VERSION 5.8 ;
BUSBITCHARS "[]" ;
DIVIDERCHAR "/" ;
UNITS
    DATABASE MICRONS 1000 ;
END UNITS

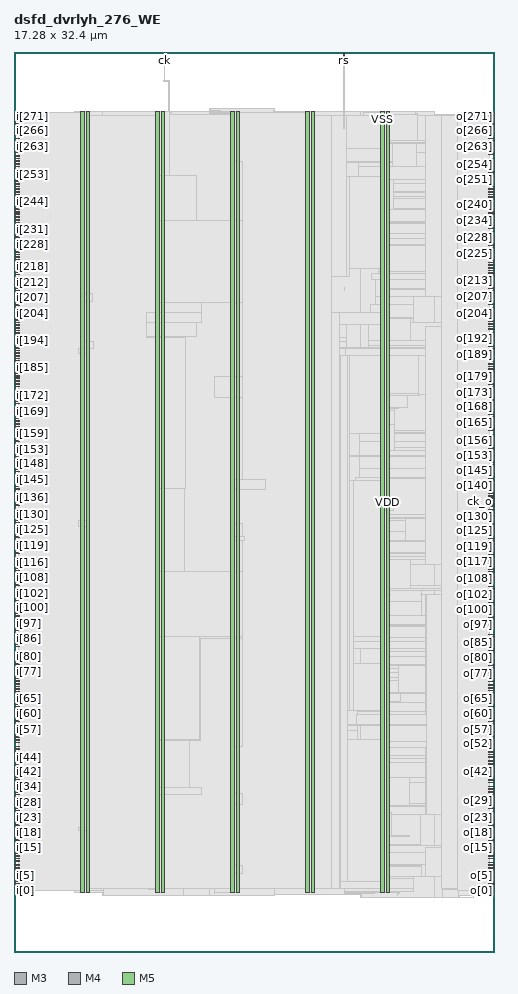
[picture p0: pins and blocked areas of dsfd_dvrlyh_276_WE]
MACRO dsfd_dvrlyh_276_WE
  FOREIGN dsfd_dvrlyh_276_WE 0 0 ;
  CLASS BLOCK ;
  SIZE 17.28 BY 32.4 ;
  PIN ck
    DIRECTION INPUT ;
    USE SIGNAL ;
    PORT
      LAYER M3 ;
        RECT  5.4 32.256 5.418 32.4 ;
    END
  END ck
  PIN ck_o
    DIRECTION OUTPUT ;
    USE SIGNAL ;
    PORT
      LAYER M4 ;
        RECT  17.088 16.224 17.28 16.248 ;
    END
  END ck_o
  PIN i[0]
    DIRECTION INPUT ;
    USE SIGNAL ;
    PORT
      LAYER M4 ;
        RECT  0 2.208 0.192 2.232 ;
    END
  END i[0]
  PIN i[100]
    DIRECTION INPUT ;
    USE SIGNAL ;
    PORT
      LAYER M4 ;
        RECT  0 12.384 0.192 12.408 ;
    END
  END i[100]
  PIN i[101]
    DIRECTION INPUT ;
    USE SIGNAL ;
    PORT
      LAYER M4 ;
        RECT  0 12.48 0.192 12.504 ;
    END
  END i[101]
  PIN i[102]
    DIRECTION INPUT ;
    USE SIGNAL ;
    PORT
      LAYER M4 ;
        RECT  0 12.624 0.192 12.648 ;
    END
  END i[102]
  PIN i[103]
    DIRECTION INPUT ;
    USE SIGNAL ;
    PORT
      LAYER M4 ;
        RECT  0 12.72 0.192 12.744 ;
    END
  END i[103]
  PIN i[104]
    DIRECTION INPUT ;
    USE SIGNAL ;
    PORT
      LAYER M4 ;
        RECT  0 12.816 0.192 12.84 ;
    END
  END i[104]
  PIN i[105]
    DIRECTION INPUT ;
    USE SIGNAL ;
    PORT
      LAYER M4 ;
        RECT  0 12.912 0.192 12.936 ;
    END
  END i[105]
  PIN i[106]
    DIRECTION INPUT ;
    USE SIGNAL ;
    PORT
      LAYER M4 ;
        RECT  0 13.008 0.192 13.032 ;
    END
  END i[106]
  PIN i[107]
    DIRECTION INPUT ;
    USE SIGNAL ;
    PORT
      LAYER M4 ;
        RECT  0 13.104 0.192 13.128 ;
    END
  END i[107]
  PIN i[108]
    DIRECTION INPUT ;
    USE SIGNAL ;
    PORT
      LAYER M4 ;
        RECT  0 13.2 0.192 13.224 ;
    END
  END i[108]
  PIN i[109]
    DIRECTION INPUT ;
    USE SIGNAL ;
    PORT
      LAYER M4 ;
        RECT  0 13.296 0.192 13.32 ;
    END
  END i[109]
  PIN i[10]
    DIRECTION INPUT ;
    USE SIGNAL ;
    PORT
      LAYER M4 ;
        RECT  0 3.264 0.192 3.288 ;
    END
  END i[10]
  PIN i[110]
    DIRECTION INPUT ;
    USE SIGNAL ;
    PORT
      LAYER M4 ;
        RECT  0 13.392 0.192 13.416 ;
    END
  END i[110]
  PIN i[111]
    DIRECTION INPUT ;
    USE SIGNAL ;
    PORT
      LAYER M4 ;
        RECT  0 13.536 0.192 13.56 ;
    END
  END i[111]
  PIN i[112]
    DIRECTION INPUT ;
    USE SIGNAL ;
    PORT
      LAYER M4 ;
        RECT  0 13.632 0.192 13.656 ;
    END
  END i[112]
  PIN i[113]
    DIRECTION INPUT ;
    USE SIGNAL ;
    PORT
      LAYER M4 ;
        RECT  0 13.728 0.192 13.752 ;
    END
  END i[113]
  PIN i[114]
    DIRECTION INPUT ;
    USE SIGNAL ;
    PORT
      LAYER M4 ;
        RECT  0 13.824 0.192 13.848 ;
    END
  END i[114]
  PIN i[115]
    DIRECTION INPUT ;
    USE SIGNAL ;
    PORT
      LAYER M4 ;
        RECT  0 13.92 0.192 13.944 ;
    END
  END i[115]
  PIN i[116]
    DIRECTION INPUT ;
    USE SIGNAL ;
    PORT
      LAYER M4 ;
        RECT  0 14.016 0.192 14.04 ;
    END
  END i[116]
  PIN i[117]
    DIRECTION INPUT ;
    USE SIGNAL ;
    PORT
      LAYER M4 ;
        RECT  0 14.112 0.192 14.136 ;
    END
  END i[117]
  PIN i[118]
    DIRECTION INPUT ;
    USE SIGNAL ;
    PORT
      LAYER M4 ;
        RECT  0 14.208 0.192 14.232 ;
    END
  END i[118]
  PIN i[119]
    DIRECTION INPUT ;
    USE SIGNAL ;
    PORT
      LAYER M4 ;
        RECT  0 14.352 0.192 14.376 ;
    END
  END i[119]
  PIN i[11]
    DIRECTION INPUT ;
    USE SIGNAL ;
    PORT
      LAYER M4 ;
        RECT  0 3.36 0.192 3.384 ;
    END
  END i[11]
  PIN i[120]
    DIRECTION INPUT ;
    USE SIGNAL ;
    PORT
      LAYER M4 ;
        RECT  0 14.448 0.192 14.472 ;
    END
  END i[120]
  PIN i[121]
    DIRECTION INPUT ;
    USE SIGNAL ;
    PORT
      LAYER M4 ;
        RECT  0 14.544 0.192 14.568 ;
    END
  END i[121]
  PIN i[122]
    DIRECTION INPUT ;
    USE SIGNAL ;
    PORT
      LAYER M4 ;
        RECT  0 14.64 0.192 14.664 ;
    END
  END i[122]
  PIN i[123]
    DIRECTION INPUT ;
    USE SIGNAL ;
    PORT
      LAYER M4 ;
        RECT  0 14.736 0.192 14.76 ;
    END
  END i[123]
  PIN i[124]
    DIRECTION INPUT ;
    USE SIGNAL ;
    PORT
      LAYER M4 ;
        RECT  0 14.832 0.192 14.856 ;
    END
  END i[124]
  PIN i[125]
    DIRECTION INPUT ;
    USE SIGNAL ;
    PORT
      LAYER M4 ;
        RECT  0 14.928 0.192 14.952 ;
    END
  END i[125]
  PIN i[126]
    DIRECTION INPUT ;
    USE SIGNAL ;
    PORT
      LAYER M4 ;
        RECT  0 15.024 0.192 15.048 ;
    END
  END i[126]
  PIN i[127]
    DIRECTION INPUT ;
    USE SIGNAL ;
    PORT
      LAYER M4 ;
        RECT  0 15.12 0.192 15.144 ;
    END
  END i[127]
  PIN i[128]
    DIRECTION INPUT ;
    USE SIGNAL ;
    PORT
      LAYER M4 ;
        RECT  0 15.264 0.192 15.288 ;
    END
  END i[128]
  PIN i[129]
    DIRECTION INPUT ;
    USE SIGNAL ;
    PORT
      LAYER M4 ;
        RECT  0 15.36 0.192 15.384 ;
    END
  END i[129]
  PIN i[12]
    DIRECTION INPUT ;
    USE SIGNAL ;
    PORT
      LAYER M4 ;
        RECT  0 3.456 0.192 3.48 ;
    END
  END i[12]
  PIN i[130]
    DIRECTION INPUT ;
    USE SIGNAL ;
    PORT
      LAYER M4 ;
        RECT  0 15.456 0.192 15.48 ;
    END
  END i[130]
  PIN i[131]
    DIRECTION INPUT ;
    USE SIGNAL ;
    PORT
      LAYER M4 ;
        RECT  0 15.552 0.192 15.576 ;
    END
  END i[131]
  PIN i[132]
    DIRECTION INPUT ;
    USE SIGNAL ;
    PORT
      LAYER M4 ;
        RECT  0 15.648 0.192 15.672 ;
    END
  END i[132]
  PIN i[133]
    DIRECTION INPUT ;
    USE SIGNAL ;
    PORT
      LAYER M4 ;
        RECT  0 15.744 0.192 15.768 ;
    END
  END i[133]
  PIN i[134]
    DIRECTION INPUT ;
    USE SIGNAL ;
    PORT
      LAYER M4 ;
        RECT  0 15.84 0.192 15.864 ;
    END
  END i[134]
  PIN i[135]
    DIRECTION INPUT ;
    USE SIGNAL ;
    PORT
      LAYER M4 ;
        RECT  0 15.936 0.192 15.96 ;
    END
  END i[135]
  PIN i[136]
    DIRECTION INPUT ;
    USE SIGNAL ;
    PORT
      LAYER M4 ;
        RECT  0 16.08 0.192 16.104 ;
    END
  END i[136]
  PIN i[137]
    DIRECTION INPUT ;
    USE SIGNAL ;
    PORT
      LAYER M4 ;
        RECT  0 16.176 0.192 16.2 ;
    END
  END i[137]
  PIN i[138]
    DIRECTION INPUT ;
    USE SIGNAL ;
    PORT
      LAYER M4 ;
        RECT  0 16.272 0.192 16.296 ;
    END
  END i[138]
  PIN i[139]
    DIRECTION INPUT ;
    USE SIGNAL ;
    PORT
      LAYER M4 ;
        RECT  0 16.368 0.192 16.392 ;
    END
  END i[139]
  PIN i[13]
    DIRECTION INPUT ;
    USE SIGNAL ;
    PORT
      LAYER M4 ;
        RECT  0 3.552 0.192 3.576 ;
    END
  END i[13]
  PIN i[140]
    DIRECTION INPUT ;
    USE SIGNAL ;
    PORT
      LAYER M4 ;
        RECT  0 16.464 0.192 16.488 ;
    END
  END i[140]
  PIN i[141]
    DIRECTION INPUT ;
    USE SIGNAL ;
    PORT
      LAYER M4 ;
        RECT  0 16.56 0.192 16.584 ;
    END
  END i[141]
  PIN i[142]
    DIRECTION INPUT ;
    USE SIGNAL ;
    PORT
      LAYER M4 ;
        RECT  0 16.656 0.192 16.68 ;
    END
  END i[142]
  PIN i[143]
    DIRECTION INPUT ;
    USE SIGNAL ;
    PORT
      LAYER M4 ;
        RECT  0 16.752 0.192 16.776 ;
    END
  END i[143]
  PIN i[144]
    DIRECTION INPUT ;
    USE SIGNAL ;
    PORT
      LAYER M4 ;
        RECT  0 16.896 0.192 16.92 ;
    END
  END i[144]
  PIN i[145]
    DIRECTION INPUT ;
    USE SIGNAL ;
    PORT
      LAYER M4 ;
        RECT  0 16.992 0.192 17.016 ;
    END
  END i[145]
  PIN i[146]
    DIRECTION INPUT ;
    USE SIGNAL ;
    PORT
      LAYER M4 ;
        RECT  0 17.088 0.192 17.112 ;
    END
  END i[146]
  PIN i[147]
    DIRECTION INPUT ;
    USE SIGNAL ;
    PORT
      LAYER M4 ;
        RECT  0 17.184 0.192 17.208 ;
    END
  END i[147]
  PIN i[148]
    DIRECTION INPUT ;
    USE SIGNAL ;
    PORT
      LAYER M4 ;
        RECT  0 17.28 0.192 17.304 ;
    END
  END i[148]
  PIN i[149]
    DIRECTION INPUT ;
    USE SIGNAL ;
    PORT
      LAYER M4 ;
        RECT  0 17.376 0.192 17.4 ;
    END
  END i[149]
  PIN i[14]
    DIRECTION INPUT ;
    USE SIGNAL ;
    PORT
      LAYER M4 ;
        RECT  0 3.648 0.192 3.672 ;
    END
  END i[14]
  PIN i[150]
    DIRECTION INPUT ;
    USE SIGNAL ;
    PORT
      LAYER M4 ;
        RECT  0 17.472 0.192 17.496 ;
    END
  END i[150]
  PIN i[151]
    DIRECTION INPUT ;
    USE SIGNAL ;
    PORT
      LAYER M4 ;
        RECT  0 17.568 0.192 17.592 ;
    END
  END i[151]
  PIN i[152]
    DIRECTION INPUT ;
    USE SIGNAL ;
    PORT
      LAYER M4 ;
        RECT  0 17.664 0.192 17.688 ;
    END
  END i[152]
  PIN i[153]
    DIRECTION INPUT ;
    USE SIGNAL ;
    PORT
      LAYER M4 ;
        RECT  0 17.808 0.192 17.832 ;
    END
  END i[153]
  PIN i[154]
    DIRECTION INPUT ;
    USE SIGNAL ;
    PORT
      LAYER M4 ;
        RECT  0 17.904 0.192 17.928 ;
    END
  END i[154]
  PIN i[155]
    DIRECTION INPUT ;
    USE SIGNAL ;
    PORT
      LAYER M4 ;
        RECT  0 18 0.192 18.024 ;
    END
  END i[155]
  PIN i[156]
    DIRECTION INPUT ;
    USE SIGNAL ;
    PORT
      LAYER M4 ;
        RECT  0 18.096 0.192 18.12 ;
    END
  END i[156]
  PIN i[157]
    DIRECTION INPUT ;
    USE SIGNAL ;
    PORT
      LAYER M4 ;
        RECT  0 18.192 0.192 18.216 ;
    END
  END i[157]
  PIN i[158]
    DIRECTION INPUT ;
    USE SIGNAL ;
    PORT
      LAYER M4 ;
        RECT  0 18.288 0.192 18.312 ;
    END
  END i[158]
  PIN i[159]
    DIRECTION INPUT ;
    USE SIGNAL ;
    PORT
      LAYER M4 ;
        RECT  0 18.384 0.192 18.408 ;
    END
  END i[159]
  PIN i[15]
    DIRECTION INPUT ;
    USE SIGNAL ;
    PORT
      LAYER M4 ;
        RECT  0 3.744 0.192 3.768 ;
    END
  END i[15]
  PIN i[160]
    DIRECTION INPUT ;
    USE SIGNAL ;
    PORT
      LAYER M4 ;
        RECT  0 18.48 0.192 18.504 ;
    END
  END i[160]
  PIN i[161]
    DIRECTION INPUT ;
    USE SIGNAL ;
    PORT
      LAYER M4 ;
        RECT  0 18.624 0.192 18.648 ;
    END
  END i[161]
  PIN i[162]
    DIRECTION INPUT ;
    USE SIGNAL ;
    PORT
      LAYER M4 ;
        RECT  0 18.72 0.192 18.744 ;
    END
  END i[162]
  PIN i[163]
    DIRECTION INPUT ;
    USE SIGNAL ;
    PORT
      LAYER M4 ;
        RECT  0 18.816 0.192 18.84 ;
    END
  END i[163]
  PIN i[164]
    DIRECTION INPUT ;
    USE SIGNAL ;
    PORT
      LAYER M4 ;
        RECT  0 18.912 0.192 18.936 ;
    END
  END i[164]
  PIN i[165]
    DIRECTION INPUT ;
    USE SIGNAL ;
    PORT
      LAYER M4 ;
        RECT  0 19.008 0.192 19.032 ;
    END
  END i[165]
  PIN i[166]
    DIRECTION INPUT ;
    USE SIGNAL ;
    PORT
      LAYER M4 ;
        RECT  0 19.104 0.192 19.128 ;
    END
  END i[166]
  PIN i[167]
    DIRECTION INPUT ;
    USE SIGNAL ;
    PORT
      LAYER M4 ;
        RECT  0 19.2 0.192 19.224 ;
    END
  END i[167]
  PIN i[168]
    DIRECTION INPUT ;
    USE SIGNAL ;
    PORT
      LAYER M4 ;
        RECT  0 19.296 0.192 19.32 ;
    END
  END i[168]
  PIN i[169]
    DIRECTION INPUT ;
    USE SIGNAL ;
    PORT
      LAYER M4 ;
        RECT  0 19.44 0.192 19.464 ;
    END
  END i[169]
  PIN i[16]
    DIRECTION INPUT ;
    USE SIGNAL ;
    PORT
      LAYER M4 ;
        RECT  0 3.84 0.192 3.864 ;
    END
  END i[16]
  PIN i[170]
    DIRECTION INPUT ;
    USE SIGNAL ;
    PORT
      LAYER M4 ;
        RECT  0 19.536 0.192 19.56 ;
    END
  END i[170]
  PIN i[171]
    DIRECTION INPUT ;
    USE SIGNAL ;
    PORT
      LAYER M4 ;
        RECT  0 19.632 0.192 19.656 ;
    END
  END i[171]
  PIN i[172]
    DIRECTION INPUT ;
    USE SIGNAL ;
    PORT
      LAYER M4 ;
        RECT  0 19.728 0.192 19.752 ;
    END
  END i[172]
  PIN i[173]
    DIRECTION INPUT ;
    USE SIGNAL ;
    PORT
      LAYER M4 ;
        RECT  0 19.824 0.192 19.848 ;
    END
  END i[173]
  PIN i[174]
    DIRECTION INPUT ;
    USE SIGNAL ;
    PORT
      LAYER M4 ;
        RECT  0 19.92 0.192 19.944 ;
    END
  END i[174]
  PIN i[175]
    DIRECTION INPUT ;
    USE SIGNAL ;
    PORT
      LAYER M4 ;
        RECT  0 20.016 0.192 20.04 ;
    END
  END i[175]
  PIN i[176]
    DIRECTION INPUT ;
    USE SIGNAL ;
    PORT
      LAYER M4 ;
        RECT  0 20.112 0.192 20.136 ;
    END
  END i[176]
  PIN i[177]
    DIRECTION INPUT ;
    USE SIGNAL ;
    PORT
      LAYER M4 ;
        RECT  0 20.208 0.192 20.232 ;
    END
  END i[177]
  PIN i[178]
    DIRECTION INPUT ;
    USE SIGNAL ;
    PORT
      LAYER M4 ;
        RECT  0 20.352 0.192 20.376 ;
    END
  END i[178]
  PIN i[179]
    DIRECTION INPUT ;
    USE SIGNAL ;
    PORT
      LAYER M4 ;
        RECT  0 20.448 0.192 20.472 ;
    END
  END i[179]
  PIN i[17]
    DIRECTION INPUT ;
    USE SIGNAL ;
    PORT
      LAYER M4 ;
        RECT  0 3.936 0.192 3.96 ;
    END
  END i[17]
  PIN i[180]
    DIRECTION INPUT ;
    USE SIGNAL ;
    PORT
      LAYER M4 ;
        RECT  0 20.544 0.192 20.568 ;
    END
  END i[180]
  PIN i[181]
    DIRECTION INPUT ;
    USE SIGNAL ;
    PORT
      LAYER M4 ;
        RECT  0 20.64 0.192 20.664 ;
    END
  END i[181]
  PIN i[182]
    DIRECTION INPUT ;
    USE SIGNAL ;
    PORT
      LAYER M4 ;
        RECT  0 20.736 0.192 20.76 ;
    END
  END i[182]
  PIN i[183]
    DIRECTION INPUT ;
    USE SIGNAL ;
    PORT
      LAYER M4 ;
        RECT  0 20.832 0.192 20.856 ;
    END
  END i[183]
  PIN i[184]
    DIRECTION INPUT ;
    USE SIGNAL ;
    PORT
      LAYER M4 ;
        RECT  0 20.928 0.192 20.952 ;
    END
  END i[184]
  PIN i[185]
    DIRECTION INPUT ;
    USE SIGNAL ;
    PORT
      LAYER M4 ;
        RECT  0 21.024 0.192 21.048 ;
    END
  END i[185]
  PIN i[186]
    DIRECTION INPUT ;
    USE SIGNAL ;
    PORT
      LAYER M4 ;
        RECT  0 21.168 0.192 21.192 ;
    END
  END i[186]
  PIN i[187]
    DIRECTION INPUT ;
    USE SIGNAL ;
    PORT
      LAYER M4 ;
        RECT  0 21.264 0.192 21.288 ;
    END
  END i[187]
  PIN i[188]
    DIRECTION INPUT ;
    USE SIGNAL ;
    PORT
      LAYER M4 ;
        RECT  0 21.36 0.192 21.384 ;
    END
  END i[188]
  PIN i[189]
    DIRECTION INPUT ;
    USE SIGNAL ;
    PORT
      LAYER M4 ;
        RECT  0 21.456 0.192 21.48 ;
    END
  END i[189]
  PIN i[18]
    DIRECTION INPUT ;
    USE SIGNAL ;
    PORT
      LAYER M4 ;
        RECT  0 4.032 0.192 4.056 ;
    END
  END i[18]
  PIN i[190]
    DIRECTION INPUT ;
    USE SIGNAL ;
    PORT
      LAYER M4 ;
        RECT  0 21.552 0.192 21.576 ;
    END
  END i[190]
  PIN i[191]
    DIRECTION INPUT ;
    USE SIGNAL ;
    PORT
      LAYER M4 ;
        RECT  0 21.648 0.192 21.672 ;
    END
  END i[191]
  PIN i[192]
    DIRECTION INPUT ;
    USE SIGNAL ;
    PORT
      LAYER M4 ;
        RECT  0 21.744 0.192 21.768 ;
    END
  END i[192]
  PIN i[193]
    DIRECTION INPUT ;
    USE SIGNAL ;
    PORT
      LAYER M4 ;
        RECT  0 21.84 0.192 21.864 ;
    END
  END i[193]
  PIN i[194]
    DIRECTION INPUT ;
    USE SIGNAL ;
    PORT
      LAYER M4 ;
        RECT  0 21.984 0.192 22.008 ;
    END
  END i[194]
  PIN i[195]
    DIRECTION INPUT ;
    USE SIGNAL ;
    PORT
      LAYER M4 ;
        RECT  0 22.08 0.192 22.104 ;
    END
  END i[195]
  PIN i[196]
    DIRECTION INPUT ;
    USE SIGNAL ;
    PORT
      LAYER M4 ;
        RECT  0 22.176 0.192 22.2 ;
    END
  END i[196]
  PIN i[197]
    DIRECTION INPUT ;
    USE SIGNAL ;
    PORT
      LAYER M4 ;
        RECT  0 22.272 0.192 22.296 ;
    END
  END i[197]
  PIN i[198]
    DIRECTION INPUT ;
    USE SIGNAL ;
    PORT
      LAYER M4 ;
        RECT  0 22.368 0.192 22.392 ;
    END
  END i[198]
  PIN i[199]
    DIRECTION INPUT ;
    USE SIGNAL ;
    PORT
      LAYER M4 ;
        RECT  0 22.464 0.192 22.488 ;
    END
  END i[199]
  PIN i[19]
    DIRECTION INPUT ;
    USE SIGNAL ;
    PORT
      LAYER M4 ;
        RECT  0 4.176 0.192 4.2 ;
    END
  END i[19]
  PIN i[1]
    DIRECTION INPUT ;
    USE SIGNAL ;
    PORT
      LAYER M4 ;
        RECT  0 2.304 0.192 2.328 ;
    END
  END i[1]
  PIN i[200]
    DIRECTION INPUT ;
    USE SIGNAL ;
    PORT
      LAYER M4 ;
        RECT  0 22.56 0.192 22.584 ;
    END
  END i[200]
  PIN i[201]
    DIRECTION INPUT ;
    USE SIGNAL ;
    PORT
      LAYER M4 ;
        RECT  0 22.656 0.192 22.68 ;
    END
  END i[201]
  PIN i[202]
    DIRECTION INPUT ;
    USE SIGNAL ;
    PORT
      LAYER M4 ;
        RECT  0 22.752 0.192 22.776 ;
    END
  END i[202]
  PIN i[203]
    DIRECTION INPUT ;
    USE SIGNAL ;
    PORT
      LAYER M4 ;
        RECT  0 22.896 0.192 22.92 ;
    END
  END i[203]
  PIN i[204]
    DIRECTION INPUT ;
    USE SIGNAL ;
    PORT
      LAYER M4 ;
        RECT  0 22.992 0.192 23.016 ;
    END
  END i[204]
  PIN i[205]
    DIRECTION INPUT ;
    USE SIGNAL ;
    PORT
      LAYER M4 ;
        RECT  0 23.088 0.192 23.112 ;
    END
  END i[205]
  PIN i[206]
    DIRECTION INPUT ;
    USE SIGNAL ;
    PORT
      LAYER M4 ;
        RECT  0 23.184 0.192 23.208 ;
    END
  END i[206]
  PIN i[207]
    DIRECTION INPUT ;
    USE SIGNAL ;
    PORT
      LAYER M4 ;
        RECT  0 23.28 0.192 23.304 ;
    END
  END i[207]
  PIN i[208]
    DIRECTION INPUT ;
    USE SIGNAL ;
    PORT
      LAYER M4 ;
        RECT  0 23.376 0.192 23.4 ;
    END
  END i[208]
  PIN i[209]
    DIRECTION INPUT ;
    USE SIGNAL ;
    PORT
      LAYER M4 ;
        RECT  0 23.472 0.192 23.496 ;
    END
  END i[209]
  PIN i[20]
    DIRECTION INPUT ;
    USE SIGNAL ;
    PORT
      LAYER M4 ;
        RECT  0 4.272 0.192 4.296 ;
    END
  END i[20]
  PIN i[210]
    DIRECTION INPUT ;
    USE SIGNAL ;
    PORT
      LAYER M4 ;
        RECT  0 23.568 0.192 23.592 ;
    END
  END i[210]
  PIN i[211]
    DIRECTION INPUT ;
    USE SIGNAL ;
    PORT
      LAYER M4 ;
        RECT  0 23.712 0.192 23.736 ;
    END
  END i[211]
  PIN i[212]
    DIRECTION INPUT ;
    USE SIGNAL ;
    PORT
      LAYER M4 ;
        RECT  0 23.808 0.192 23.832 ;
    END
  END i[212]
  PIN i[213]
    DIRECTION INPUT ;
    USE SIGNAL ;
    PORT
      LAYER M4 ;
        RECT  0 23.904 0.192 23.928 ;
    END
  END i[213]
  PIN i[214]
    DIRECTION INPUT ;
    USE SIGNAL ;
    PORT
      LAYER M4 ;
        RECT  0 24 0.192 24.024 ;
    END
  END i[214]
  PIN i[215]
    DIRECTION INPUT ;
    USE SIGNAL ;
    PORT
      LAYER M4 ;
        RECT  0 24.096 0.192 24.12 ;
    END
  END i[215]
  PIN i[216]
    DIRECTION INPUT ;
    USE SIGNAL ;
    PORT
      LAYER M4 ;
        RECT  0 24.192 0.192 24.216 ;
    END
  END i[216]
  PIN i[217]
    DIRECTION INPUT ;
    USE SIGNAL ;
    PORT
      LAYER M4 ;
        RECT  0 24.288 0.192 24.312 ;
    END
  END i[217]
  PIN i[218]
    DIRECTION INPUT ;
    USE SIGNAL ;
    PORT
      LAYER M4 ;
        RECT  0 24.384 0.192 24.408 ;
    END
  END i[218]
  PIN i[219]
    DIRECTION INPUT ;
    USE SIGNAL ;
    PORT
      LAYER M4 ;
        RECT  0 24.48 0.192 24.504 ;
    END
  END i[219]
  PIN i[21]
    DIRECTION INPUT ;
    USE SIGNAL ;
    PORT
      LAYER M4 ;
        RECT  0 4.368 0.192 4.392 ;
    END
  END i[21]
  PIN i[220]
    DIRECTION INPUT ;
    USE SIGNAL ;
    PORT
      LAYER M4 ;
        RECT  0 24.624 0.192 24.648 ;
    END
  END i[220]
  PIN i[221]
    DIRECTION INPUT ;
    USE SIGNAL ;
    PORT
      LAYER M4 ;
        RECT  0 24.72 0.192 24.744 ;
    END
  END i[221]
  PIN i[222]
    DIRECTION INPUT ;
    USE SIGNAL ;
    PORT
      LAYER M4 ;
        RECT  0 24.816 0.192 24.84 ;
    END
  END i[222]
  PIN i[223]
    DIRECTION INPUT ;
    USE SIGNAL ;
    PORT
      LAYER M4 ;
        RECT  0 24.912 0.192 24.936 ;
    END
  END i[223]
  PIN i[224]
    DIRECTION INPUT ;
    USE SIGNAL ;
    PORT
      LAYER M4 ;
        RECT  0 25.008 0.192 25.032 ;
    END
  END i[224]
  PIN i[225]
    DIRECTION INPUT ;
    USE SIGNAL ;
    PORT
      LAYER M4 ;
        RECT  0 25.104 0.192 25.128 ;
    END
  END i[225]
  PIN i[226]
    DIRECTION INPUT ;
    USE SIGNAL ;
    PORT
      LAYER M4 ;
        RECT  0 25.2 0.192 25.224 ;
    END
  END i[226]
  PIN i[227]
    DIRECTION INPUT ;
    USE SIGNAL ;
    PORT
      LAYER M4 ;
        RECT  0 25.296 0.192 25.32 ;
    END
  END i[227]
  PIN i[228]
    DIRECTION INPUT ;
    USE SIGNAL ;
    PORT
      LAYER M4 ;
        RECT  0 25.44 0.192 25.464 ;
    END
  END i[228]
  PIN i[229]
    DIRECTION INPUT ;
    USE SIGNAL ;
    PORT
      LAYER M4 ;
        RECT  0 25.536 0.192 25.56 ;
    END
  END i[229]
  PIN i[22]
    DIRECTION INPUT ;
    USE SIGNAL ;
    PORT
      LAYER M4 ;
        RECT  0 4.464 0.192 4.488 ;
    END
  END i[22]
  PIN i[230]
    DIRECTION INPUT ;
    USE SIGNAL ;
    PORT
      LAYER M4 ;
        RECT  0 25.632 0.192 25.656 ;
    END
  END i[230]
  PIN i[231]
    DIRECTION INPUT ;
    USE SIGNAL ;
    PORT
      LAYER M4 ;
        RECT  0 25.728 0.192 25.752 ;
    END
  END i[231]
  PIN i[232]
    DIRECTION INPUT ;
    USE SIGNAL ;
    PORT
      LAYER M4 ;
        RECT  0 25.824 0.192 25.848 ;
    END
  END i[232]
  PIN i[233]
    DIRECTION INPUT ;
    USE SIGNAL ;
    PORT
      LAYER M4 ;
        RECT  0 25.92 0.192 25.944 ;
    END
  END i[233]
  PIN i[234]
    DIRECTION INPUT ;
    USE SIGNAL ;
    PORT
      LAYER M4 ;
        RECT  0 26.016 0.192 26.04 ;
    END
  END i[234]
  PIN i[235]
    DIRECTION INPUT ;
    USE SIGNAL ;
    PORT
      LAYER M4 ;
        RECT  0 26.112 0.192 26.136 ;
    END
  END i[235]
  PIN i[236]
    DIRECTION INPUT ;
    USE SIGNAL ;
    PORT
      LAYER M4 ;
        RECT  0 26.256 0.192 26.28 ;
    END
  END i[236]
  PIN i[237]
    DIRECTION INPUT ;
    USE SIGNAL ;
    PORT
      LAYER M4 ;
        RECT  0 26.352 0.192 26.376 ;
    END
  END i[237]
  PIN i[238]
    DIRECTION INPUT ;
    USE SIGNAL ;
    PORT
      LAYER M4 ;
        RECT  0 26.448 0.192 26.472 ;
    END
  END i[238]
  PIN i[239]
    DIRECTION INPUT ;
    USE SIGNAL ;
    PORT
      LAYER M4 ;
        RECT  0 26.544 0.192 26.568 ;
    END
  END i[239]
  PIN i[23]
    DIRECTION INPUT ;
    USE SIGNAL ;
    PORT
      LAYER M4 ;
        RECT  0 4.56 0.192 4.584 ;
    END
  END i[23]
  PIN i[240]
    DIRECTION INPUT ;
    USE SIGNAL ;
    PORT
      LAYER M4 ;
        RECT  0 26.64 0.192 26.664 ;
    END
  END i[240]
  PIN i[241]
    DIRECTION INPUT ;
    USE SIGNAL ;
    PORT
      LAYER M4 ;
        RECT  0 26.736 0.192 26.76 ;
    END
  END i[241]
  PIN i[242]
    DIRECTION INPUT ;
    USE SIGNAL ;
    PORT
      LAYER M4 ;
        RECT  0 26.832 0.192 26.856 ;
    END
  END i[242]
  PIN i[243]
    DIRECTION INPUT ;
    USE SIGNAL ;
    PORT
      LAYER M4 ;
        RECT  0 26.928 0.192 26.952 ;
    END
  END i[243]
  PIN i[244]
    DIRECTION INPUT ;
    USE SIGNAL ;
    PORT
      LAYER M4 ;
        RECT  0 27.024 0.192 27.048 ;
    END
  END i[244]
  PIN i[245]
    DIRECTION INPUT ;
    USE SIGNAL ;
    PORT
      LAYER M4 ;
        RECT  0 27.168 0.192 27.192 ;
    END
  END i[245]
  PIN i[246]
    DIRECTION INPUT ;
    USE SIGNAL ;
    PORT
      LAYER M4 ;
        RECT  0 27.264 0.192 27.288 ;
    END
  END i[246]
  PIN i[247]
    DIRECTION INPUT ;
    USE SIGNAL ;
    PORT
      LAYER M4 ;
        RECT  0 27.36 0.192 27.384 ;
    END
  END i[247]
  PIN i[248]
    DIRECTION INPUT ;
    USE SIGNAL ;
    PORT
      LAYER M4 ;
        RECT  0 27.456 0.192 27.48 ;
    END
  END i[248]
  PIN i[249]
    DIRECTION INPUT ;
    USE SIGNAL ;
    PORT
      LAYER M4 ;
        RECT  0 27.552 0.192 27.576 ;
    END
  END i[249]
  PIN i[24]
    DIRECTION INPUT ;
    USE SIGNAL ;
    PORT
      LAYER M4 ;
        RECT  0 4.656 0.192 4.68 ;
    END
  END i[24]
  PIN i[250]
    DIRECTION INPUT ;
    USE SIGNAL ;
    PORT
      LAYER M4 ;
        RECT  0 27.648 0.192 27.672 ;
    END
  END i[250]
  PIN i[251]
    DIRECTION INPUT ;
    USE SIGNAL ;
    PORT
      LAYER M4 ;
        RECT  0 27.744 0.192 27.768 ;
    END
  END i[251]
  PIN i[252]
    DIRECTION INPUT ;
    USE SIGNAL ;
    PORT
      LAYER M4 ;
        RECT  0 27.84 0.192 27.864 ;
    END
  END i[252]
  PIN i[253]
    DIRECTION INPUT ;
    USE SIGNAL ;
    PORT
      LAYER M4 ;
        RECT  0 27.984 0.192 28.008 ;
    END
  END i[253]
  PIN i[254]
    DIRECTION INPUT ;
    USE SIGNAL ;
    PORT
      LAYER M4 ;
        RECT  0 28.08 0.192 28.104 ;
    END
  END i[254]
  PIN i[255]
    DIRECTION INPUT ;
    USE SIGNAL ;
    PORT
      LAYER M4 ;
        RECT  0 28.176 0.192 28.2 ;
    END
  END i[255]
  PIN i[256]
    DIRECTION INPUT ;
    USE SIGNAL ;
    PORT
      LAYER M4 ;
        RECT  0 28.272 0.192 28.296 ;
    END
  END i[256]
  PIN i[257]
    DIRECTION INPUT ;
    USE SIGNAL ;
    PORT
      LAYER M4 ;
        RECT  0 28.368 0.192 28.392 ;
    END
  END i[257]
  PIN i[258]
    DIRECTION INPUT ;
    USE SIGNAL ;
    PORT
      LAYER M4 ;
        RECT  0 28.464 0.192 28.488 ;
    END
  END i[258]
  PIN i[259]
    DIRECTION INPUT ;
    USE SIGNAL ;
    PORT
      LAYER M4 ;
        RECT  0 28.56 0.192 28.584 ;
    END
  END i[259]
  PIN i[25]
    DIRECTION INPUT ;
    USE SIGNAL ;
    PORT
      LAYER M4 ;
        RECT  0 4.752 0.192 4.776 ;
    END
  END i[25]
  PIN i[260]
    DIRECTION INPUT ;
    USE SIGNAL ;
    PORT
      LAYER M4 ;
        RECT  0 28.656 0.192 28.68 ;
    END
  END i[260]
  PIN i[261]
    DIRECTION INPUT ;
    USE SIGNAL ;
    PORT
      LAYER M4 ;
        RECT  0 28.8 0.192 28.824 ;
    END
  END i[261]
  PIN i[262]
    DIRECTION INPUT ;
    USE SIGNAL ;
    PORT
      LAYER M4 ;
        RECT  0 28.896 0.192 28.92 ;
    END
  END i[262]
  PIN i[263]
    DIRECTION INPUT ;
    USE SIGNAL ;
    PORT
      LAYER M4 ;
        RECT  0 28.992 0.192 29.016 ;
    END
  END i[263]
  PIN i[264]
    DIRECTION INPUT ;
    USE SIGNAL ;
    PORT
      LAYER M4 ;
        RECT  0 29.088 0.192 29.112 ;
    END
  END i[264]
  PIN i[265]
    DIRECTION INPUT ;
    USE SIGNAL ;
    PORT
      LAYER M4 ;
        RECT  0 29.184 0.192 29.208 ;
    END
  END i[265]
  PIN i[266]
    DIRECTION INPUT ;
    USE SIGNAL ;
    PORT
      LAYER M4 ;
        RECT  0 29.28 0.192 29.304 ;
    END
  END i[266]
  PIN i[267]
    DIRECTION INPUT ;
    USE SIGNAL ;
    PORT
      LAYER M4 ;
        RECT  0 29.376 0.192 29.4 ;
    END
  END i[267]
  PIN i[268]
    DIRECTION INPUT ;
    USE SIGNAL ;
    PORT
      LAYER M4 ;
        RECT  0 29.472 0.192 29.496 ;
    END
  END i[268]
  PIN i[269]
    DIRECTION INPUT ;
    USE SIGNAL ;
    PORT
      LAYER M4 ;
        RECT  0 29.568 0.192 29.592 ;
    END
  END i[269]
  PIN i[26]
    DIRECTION INPUT ;
    USE SIGNAL ;
    PORT
      LAYER M4 ;
        RECT  0 4.848 0.192 4.872 ;
    END
  END i[26]
  PIN i[270]
    DIRECTION INPUT ;
    USE SIGNAL ;
    PORT
      LAYER M4 ;
        RECT  0 29.712 0.192 29.736 ;
    END
  END i[270]
  PIN i[271]
    DIRECTION INPUT ;
    USE SIGNAL ;
    PORT
      LAYER M4 ;
        RECT  0 29.808 0.192 29.832 ;
    END
  END i[271]
  PIN i[272]
    DIRECTION INPUT ;
    USE SIGNAL ;
    PORT
      LAYER M4 ;
        RECT  0 29.904 0.192 29.928 ;
    END
  END i[272]
  PIN i[273]
    DIRECTION INPUT ;
    USE SIGNAL ;
    PORT
      LAYER M4 ;
        RECT  0 30 0.192 30.024 ;
    END
  END i[273]
  PIN i[274]
    DIRECTION INPUT ;
    USE SIGNAL ;
    PORT
      LAYER M4 ;
        RECT  0 30.096 0.192 30.12 ;
    END
  END i[274]
  PIN i[275]
    DIRECTION INPUT ;
    USE SIGNAL ;
    PORT
      LAYER M4 ;
        RECT  0 30.192 0.192 30.216 ;
    END
  END i[275]
  PIN i[27]
    DIRECTION INPUT ;
    USE SIGNAL ;
    PORT
      LAYER M4 ;
        RECT  0 4.992 0.192 5.016 ;
    END
  END i[27]
  PIN i[28]
    DIRECTION INPUT ;
    USE SIGNAL ;
    PORT
      LAYER M4 ;
        RECT  0 5.088 0.192 5.112 ;
    END
  END i[28]
  PIN i[29]
    DIRECTION INPUT ;
    USE SIGNAL ;
    PORT
      LAYER M4 ;
        RECT  0 5.184 0.192 5.208 ;
    END
  END i[29]
  PIN i[2]
    DIRECTION INPUT ;
    USE SIGNAL ;
    PORT
      LAYER M4 ;
        RECT  0 2.448 0.192 2.472 ;
    END
  END i[2]
  PIN i[30]
    DIRECTION INPUT ;
    USE SIGNAL ;
    PORT
      LAYER M4 ;
        RECT  0 5.28 0.192 5.304 ;
    END
  END i[30]
  PIN i[31]
    DIRECTION INPUT ;
    USE SIGNAL ;
    PORT
      LAYER M4 ;
        RECT  0 5.376 0.192 5.4 ;
    END
  END i[31]
  PIN i[32]
    DIRECTION INPUT ;
    USE SIGNAL ;
    PORT
      LAYER M4 ;
        RECT  0 5.472 0.192 5.496 ;
    END
  END i[32]
  PIN i[33]
    DIRECTION INPUT ;
    USE SIGNAL ;
    PORT
      LAYER M4 ;
        RECT  0 5.568 0.192 5.592 ;
    END
  END i[33]
  PIN i[34]
    DIRECTION INPUT ;
    USE SIGNAL ;
    PORT
      LAYER M4 ;
        RECT  0 5.664 0.192 5.688 ;
    END
  END i[34]
  PIN i[35]
    DIRECTION INPUT ;
    USE SIGNAL ;
    PORT
      LAYER M4 ;
        RECT  0 5.76 0.192 5.784 ;
    END
  END i[35]
  PIN i[36]
    DIRECTION INPUT ;
    USE SIGNAL ;
    PORT
      LAYER M4 ;
        RECT  0 5.904 0.192 5.928 ;
    END
  END i[36]
  PIN i[37]
    DIRECTION INPUT ;
    USE SIGNAL ;
    PORT
      LAYER M4 ;
        RECT  0 6 0.192 6.024 ;
    END
  END i[37]
  PIN i[38]
    DIRECTION INPUT ;
    USE SIGNAL ;
    PORT
      LAYER M4 ;
        RECT  0 6.096 0.192 6.12 ;
    END
  END i[38]
  PIN i[39]
    DIRECTION INPUT ;
    USE SIGNAL ;
    PORT
      LAYER M4 ;
        RECT  0 6.192 0.192 6.216 ;
    END
  END i[39]
  PIN i[3]
    DIRECTION INPUT ;
    USE SIGNAL ;
    PORT
      LAYER M4 ;
        RECT  0 2.544 0.192 2.568 ;
    END
  END i[3]
  PIN i[40]
    DIRECTION INPUT ;
    USE SIGNAL ;
    PORT
      LAYER M4 ;
        RECT  0 6.288 0.192 6.312 ;
    END
  END i[40]
  PIN i[41]
    DIRECTION INPUT ;
    USE SIGNAL ;
    PORT
      LAYER M4 ;
        RECT  0 6.384 0.192 6.408 ;
    END
  END i[41]
  PIN i[42]
    DIRECTION INPUT ;
    USE SIGNAL ;
    PORT
      LAYER M4 ;
        RECT  0 6.48 0.192 6.504 ;
    END
  END i[42]
  PIN i[43]
    DIRECTION INPUT ;
    USE SIGNAL ;
    PORT
      LAYER M4 ;
        RECT  0 6.576 0.192 6.6 ;
    END
  END i[43]
  PIN i[44]
    DIRECTION INPUT ;
    USE SIGNAL ;
    PORT
      LAYER M4 ;
        RECT  0 6.72 0.192 6.744 ;
    END
  END i[44]
  PIN i[45]
    DIRECTION INPUT ;
    USE SIGNAL ;
    PORT
      LAYER M4 ;
        RECT  0 6.816 0.192 6.84 ;
    END
  END i[45]
  PIN i[46]
    DIRECTION INPUT ;
    USE SIGNAL ;
    PORT
      LAYER M4 ;
        RECT  0 6.912 0.192 6.936 ;
    END
  END i[46]
  PIN i[47]
    DIRECTION INPUT ;
    USE SIGNAL ;
    PORT
      LAYER M4 ;
        RECT  0 7.008 0.192 7.032 ;
    END
  END i[47]
  PIN i[48]
    DIRECTION INPUT ;
    USE SIGNAL ;
    PORT
      LAYER M4 ;
        RECT  0 7.104 0.192 7.128 ;
    END
  END i[48]
  PIN i[49]
    DIRECTION INPUT ;
    USE SIGNAL ;
    PORT
      LAYER M4 ;
        RECT  0 7.2 0.192 7.224 ;
    END
  END i[49]
  PIN i[4]
    DIRECTION INPUT ;
    USE SIGNAL ;
    PORT
      LAYER M4 ;
        RECT  0 2.64 0.192 2.664 ;
    END
  END i[4]
  PIN i[50]
    DIRECTION INPUT ;
    USE SIGNAL ;
    PORT
      LAYER M4 ;
        RECT  0 7.296 0.192 7.32 ;
    END
  END i[50]
  PIN i[51]
    DIRECTION INPUT ;
    USE SIGNAL ;
    PORT
      LAYER M4 ;
        RECT  0 7.392 0.192 7.416 ;
    END
  END i[51]
  PIN i[52]
    DIRECTION INPUT ;
    USE SIGNAL ;
    PORT
      LAYER M4 ;
        RECT  0 7.536 0.192 7.56 ;
    END
  END i[52]
  PIN i[53]
    DIRECTION INPUT ;
    USE SIGNAL ;
    PORT
      LAYER M4 ;
        RECT  0 7.632 0.192 7.656 ;
    END
  END i[53]
  PIN i[54]
    DIRECTION INPUT ;
    USE SIGNAL ;
    PORT
      LAYER M4 ;
        RECT  0 7.728 0.192 7.752 ;
    END
  END i[54]
  PIN i[55]
    DIRECTION INPUT ;
    USE SIGNAL ;
    PORT
      LAYER M4 ;
        RECT  0 7.824 0.192 7.848 ;
    END
  END i[55]
  PIN i[56]
    DIRECTION INPUT ;
    USE SIGNAL ;
    PORT
      LAYER M4 ;
        RECT  0 7.92 0.192 7.944 ;
    END
  END i[56]
  PIN i[57]
    DIRECTION INPUT ;
    USE SIGNAL ;
    PORT
      LAYER M4 ;
        RECT  0 8.016 0.192 8.04 ;
    END
  END i[57]
  PIN i[58]
    DIRECTION INPUT ;
    USE SIGNAL ;
    PORT
      LAYER M4 ;
        RECT  0 8.112 0.192 8.136 ;
    END
  END i[58]
  PIN i[59]
    DIRECTION INPUT ;
    USE SIGNAL ;
    PORT
      LAYER M4 ;
        RECT  0 8.208 0.192 8.232 ;
    END
  END i[59]
  PIN i[5]
    DIRECTION INPUT ;
    USE SIGNAL ;
    PORT
      LAYER M4 ;
        RECT  0 2.736 0.192 2.76 ;
    END
  END i[5]
  PIN i[60]
    DIRECTION INPUT ;
    USE SIGNAL ;
    PORT
      LAYER M4 ;
        RECT  0 8.304 0.192 8.328 ;
    END
  END i[60]
  PIN i[61]
    DIRECTION INPUT ;
    USE SIGNAL ;
    PORT
      LAYER M4 ;
        RECT  0 8.448 0.192 8.472 ;
    END
  END i[61]
  PIN i[62]
    DIRECTION INPUT ;
    USE SIGNAL ;
    PORT
      LAYER M4 ;
        RECT  0 8.544 0.192 8.568 ;
    END
  END i[62]
  PIN i[63]
    DIRECTION INPUT ;
    USE SIGNAL ;
    PORT
      LAYER M4 ;
        RECT  0 8.64 0.192 8.664 ;
    END
  END i[63]
  PIN i[64]
    DIRECTION INPUT ;
    USE SIGNAL ;
    PORT
      LAYER M4 ;
        RECT  0 8.736 0.192 8.76 ;
    END
  END i[64]
  PIN i[65]
    DIRECTION INPUT ;
    USE SIGNAL ;
    PORT
      LAYER M4 ;
        RECT  0 8.832 0.192 8.856 ;
    END
  END i[65]
  PIN i[66]
    DIRECTION INPUT ;
    USE SIGNAL ;
    PORT
      LAYER M4 ;
        RECT  0 8.928 0.192 8.952 ;
    END
  END i[66]
  PIN i[67]
    DIRECTION INPUT ;
    USE SIGNAL ;
    PORT
      LAYER M4 ;
        RECT  0 9.024 0.192 9.048 ;
    END
  END i[67]
  PIN i[68]
    DIRECTION INPUT ;
    USE SIGNAL ;
    PORT
      LAYER M4 ;
        RECT  0 9.12 0.192 9.144 ;
    END
  END i[68]
  PIN i[69]
    DIRECTION INPUT ;
    USE SIGNAL ;
    PORT
      LAYER M4 ;
        RECT  0 9.264 0.192 9.288 ;
    END
  END i[69]
  PIN i[6]
    DIRECTION INPUT ;
    USE SIGNAL ;
    PORT
      LAYER M4 ;
        RECT  0 2.832 0.192 2.856 ;
    END
  END i[6]
  PIN i[70]
    DIRECTION INPUT ;
    USE SIGNAL ;
    PORT
      LAYER M4 ;
        RECT  0 9.36 0.192 9.384 ;
    END
  END i[70]
  PIN i[71]
    DIRECTION INPUT ;
    USE SIGNAL ;
    PORT
      LAYER M4 ;
        RECT  0 9.456 0.192 9.48 ;
    END
  END i[71]
  PIN i[72]
    DIRECTION INPUT ;
    USE SIGNAL ;
    PORT
      LAYER M4 ;
        RECT  0 9.552 0.192 9.576 ;
    END
  END i[72]
  PIN i[73]
    DIRECTION INPUT ;
    USE SIGNAL ;
    PORT
      LAYER M4 ;
        RECT  0 9.648 0.192 9.672 ;
    END
  END i[73]
  PIN i[74]
    DIRECTION INPUT ;
    USE SIGNAL ;
    PORT
      LAYER M4 ;
        RECT  0 9.744 0.192 9.768 ;
    END
  END i[74]
  PIN i[75]
    DIRECTION INPUT ;
    USE SIGNAL ;
    PORT
      LAYER M4 ;
        RECT  0 9.84 0.192 9.864 ;
    END
  END i[75]
  PIN i[76]
    DIRECTION INPUT ;
    USE SIGNAL ;
    PORT
      LAYER M4 ;
        RECT  0 9.936 0.192 9.96 ;
    END
  END i[76]
  PIN i[77]
    DIRECTION INPUT ;
    USE SIGNAL ;
    PORT
      LAYER M4 ;
        RECT  0 10.08 0.192 10.104 ;
    END
  END i[77]
  PIN i[78]
    DIRECTION INPUT ;
    USE SIGNAL ;
    PORT
      LAYER M4 ;
        RECT  0 10.176 0.192 10.2 ;
    END
  END i[78]
  PIN i[79]
    DIRECTION INPUT ;
    USE SIGNAL ;
    PORT
      LAYER M4 ;
        RECT  0 10.272 0.192 10.296 ;
    END
  END i[79]
  PIN i[7]
    DIRECTION INPUT ;
    USE SIGNAL ;
    PORT
      LAYER M4 ;
        RECT  0 2.928 0.192 2.952 ;
    END
  END i[7]
  PIN i[80]
    DIRECTION INPUT ;
    USE SIGNAL ;
    PORT
      LAYER M4 ;
        RECT  0 10.368 0.192 10.392 ;
    END
  END i[80]
  PIN i[81]
    DIRECTION INPUT ;
    USE SIGNAL ;
    PORT
      LAYER M4 ;
        RECT  0 10.464 0.192 10.488 ;
    END
  END i[81]
  PIN i[82]
    DIRECTION INPUT ;
    USE SIGNAL ;
    PORT
      LAYER M4 ;
        RECT  0 10.56 0.192 10.584 ;
    END
  END i[82]
  PIN i[83]
    DIRECTION INPUT ;
    USE SIGNAL ;
    PORT
      LAYER M4 ;
        RECT  0 10.656 0.192 10.68 ;
    END
  END i[83]
  PIN i[84]
    DIRECTION INPUT ;
    USE SIGNAL ;
    PORT
      LAYER M4 ;
        RECT  0 10.752 0.192 10.776 ;
    END
  END i[84]
  PIN i[85]
    DIRECTION INPUT ;
    USE SIGNAL ;
    PORT
      LAYER M4 ;
        RECT  0 10.848 0.192 10.872 ;
    END
  END i[85]
  PIN i[86]
    DIRECTION INPUT ;
    USE SIGNAL ;
    PORT
      LAYER M4 ;
        RECT  0 10.992 0.192 11.016 ;
    END
  END i[86]
  PIN i[87]
    DIRECTION INPUT ;
    USE SIGNAL ;
    PORT
      LAYER M4 ;
        RECT  0 11.088 0.192 11.112 ;
    END
  END i[87]
  PIN i[88]
    DIRECTION INPUT ;
    USE SIGNAL ;
    PORT
      LAYER M4 ;
        RECT  0 11.184 0.192 11.208 ;
    END
  END i[88]
  PIN i[89]
    DIRECTION INPUT ;
    USE SIGNAL ;
    PORT
      LAYER M4 ;
        RECT  0 11.28 0.192 11.304 ;
    END
  END i[89]
  PIN i[8]
    DIRECTION INPUT ;
    USE SIGNAL ;
    PORT
      LAYER M4 ;
        RECT  0 3.024 0.192 3.048 ;
    END
  END i[8]
  PIN i[90]
    DIRECTION INPUT ;
    USE SIGNAL ;
    PORT
      LAYER M4 ;
        RECT  0 11.376 0.192 11.4 ;
    END
  END i[90]
  PIN i[91]
    DIRECTION INPUT ;
    USE SIGNAL ;
    PORT
      LAYER M4 ;
        RECT  0 11.472 0.192 11.496 ;
    END
  END i[91]
  PIN i[92]
    DIRECTION INPUT ;
    USE SIGNAL ;
    PORT
      LAYER M4 ;
        RECT  0 11.568 0.192 11.592 ;
    END
  END i[92]
  PIN i[93]
    DIRECTION INPUT ;
    USE SIGNAL ;
    PORT
      LAYER M4 ;
        RECT  0 11.664 0.192 11.688 ;
    END
  END i[93]
  PIN i[94]
    DIRECTION INPUT ;
    USE SIGNAL ;
    PORT
      LAYER M4 ;
        RECT  0 11.808 0.192 11.832 ;
    END
  END i[94]
  PIN i[95]
    DIRECTION INPUT ;
    USE SIGNAL ;
    PORT
      LAYER M4 ;
        RECT  0 11.904 0.192 11.928 ;
    END
  END i[95]
  PIN i[96]
    DIRECTION INPUT ;
    USE SIGNAL ;
    PORT
      LAYER M4 ;
        RECT  0 12 0.192 12.024 ;
    END
  END i[96]
  PIN i[97]
    DIRECTION INPUT ;
    USE SIGNAL ;
    PORT
      LAYER M4 ;
        RECT  0 12.096 0.192 12.12 ;
    END
  END i[97]
  PIN i[98]
    DIRECTION INPUT ;
    USE SIGNAL ;
    PORT
      LAYER M4 ;
        RECT  0 12.192 0.192 12.216 ;
    END
  END i[98]
  PIN i[99]
    DIRECTION INPUT ;
    USE SIGNAL ;
    PORT
      LAYER M4 ;
        RECT  0 12.288 0.192 12.312 ;
    END
  END i[99]
  PIN i[9]
    DIRECTION INPUT ;
    USE SIGNAL ;
    PORT
      LAYER M4 ;
        RECT  0 3.12 0.192 3.144 ;
    END
  END i[9]
  PIN o[0]
    DIRECTION OUTPUT ;
    USE SIGNAL ;
    PORT
      LAYER M4 ;
        RECT  17.088 2.208 17.28 2.232 ;
    END
  END o[0]
  PIN o[100]
    DIRECTION OUTPUT ;
    USE SIGNAL ;
    PORT
      LAYER M4 ;
        RECT  17.088 12.336 17.28 12.36 ;
    END
  END o[100]
  PIN o[101]
    DIRECTION OUTPUT ;
    USE SIGNAL ;
    PORT
      LAYER M4 ;
        RECT  17.088 12.48 17.28 12.504 ;
    END
  END o[101]
  PIN o[102]
    DIRECTION OUTPUT ;
    USE SIGNAL ;
    PORT
      LAYER M4 ;
        RECT  17.088 12.576 17.28 12.6 ;
    END
  END o[102]
  PIN o[103]
    DIRECTION OUTPUT ;
    USE SIGNAL ;
    PORT
      LAYER M4 ;
        RECT  17.088 12.672 17.28 12.696 ;
    END
  END o[103]
  PIN o[104]
    DIRECTION OUTPUT ;
    USE SIGNAL ;
    PORT
      LAYER M4 ;
        RECT  17.088 12.768 17.28 12.792 ;
    END
  END o[104]
  PIN o[105]
    DIRECTION OUTPUT ;
    USE SIGNAL ;
    PORT
      LAYER M4 ;
        RECT  17.088 12.864 17.28 12.888 ;
    END
  END o[105]
  PIN o[106]
    DIRECTION OUTPUT ;
    USE SIGNAL ;
    PORT
      LAYER M4 ;
        RECT  17.088 12.96 17.28 12.984 ;
    END
  END o[106]
  PIN o[107]
    DIRECTION OUTPUT ;
    USE SIGNAL ;
    PORT
      LAYER M4 ;
        RECT  17.088 13.056 17.28 13.08 ;
    END
  END o[107]
  PIN o[108]
    DIRECTION OUTPUT ;
    USE SIGNAL ;
    PORT
      LAYER M4 ;
        RECT  17.088 13.152 17.28 13.176 ;
    END
  END o[108]
  PIN o[109]
    DIRECTION OUTPUT ;
    USE SIGNAL ;
    PORT
      LAYER M4 ;
        RECT  17.088 13.296 17.28 13.32 ;
    END
  END o[109]
  PIN o[10]
    DIRECTION OUTPUT ;
    USE SIGNAL ;
    PORT
      LAYER M4 ;
        RECT  17.088 3.216 17.28 3.24 ;
    END
  END o[10]
  PIN o[110]
    DIRECTION OUTPUT ;
    USE SIGNAL ;
    PORT
      LAYER M4 ;
        RECT  17.088 13.392 17.28 13.416 ;
    END
  END o[110]
  PIN o[111]
    DIRECTION OUTPUT ;
    USE SIGNAL ;
    PORT
      LAYER M4 ;
        RECT  17.088 13.488 17.28 13.512 ;
    END
  END o[111]
  PIN o[112]
    DIRECTION OUTPUT ;
    USE SIGNAL ;
    PORT
      LAYER M4 ;
        RECT  17.088 13.584 17.28 13.608 ;
    END
  END o[112]
  PIN o[113]
    DIRECTION OUTPUT ;
    USE SIGNAL ;
    PORT
      LAYER M4 ;
        RECT  17.088 13.68 17.28 13.704 ;
    END
  END o[113]
  PIN o[114]
    DIRECTION OUTPUT ;
    USE SIGNAL ;
    PORT
      LAYER M4 ;
        RECT  17.088 13.776 17.28 13.8 ;
    END
  END o[114]
  PIN o[115]
    DIRECTION OUTPUT ;
    USE SIGNAL ;
    PORT
      LAYER M4 ;
        RECT  17.088 13.872 17.28 13.896 ;
    END
  END o[115]
  PIN o[116]
    DIRECTION OUTPUT ;
    USE SIGNAL ;
    PORT
      LAYER M4 ;
        RECT  17.088 13.968 17.28 13.992 ;
    END
  END o[116]
  PIN o[117]
    DIRECTION OUTPUT ;
    USE SIGNAL ;
    PORT
      LAYER M4 ;
        RECT  17.088 14.064 17.28 14.088 ;
    END
  END o[117]
  PIN o[118]
    DIRECTION OUTPUT ;
    USE SIGNAL ;
    PORT
      LAYER M4 ;
        RECT  17.088 14.208 17.28 14.232 ;
    END
  END o[118]
  PIN o[119]
    DIRECTION OUTPUT ;
    USE SIGNAL ;
    PORT
      LAYER M4 ;
        RECT  17.088 14.304 17.28 14.328 ;
    END
  END o[119]
  PIN o[11]
    DIRECTION OUTPUT ;
    USE SIGNAL ;
    PORT
      LAYER M4 ;
        RECT  17.088 3.36 17.28 3.384 ;
    END
  END o[11]
  PIN o[120]
    DIRECTION OUTPUT ;
    USE SIGNAL ;
    PORT
      LAYER M4 ;
        RECT  17.088 14.4 17.28 14.424 ;
    END
  END o[120]
  PIN o[121]
    DIRECTION OUTPUT ;
    USE SIGNAL ;
    PORT
      LAYER M4 ;
        RECT  17.088 14.496 17.28 14.52 ;
    END
  END o[121]
  PIN o[122]
    DIRECTION OUTPUT ;
    USE SIGNAL ;
    PORT
      LAYER M4 ;
        RECT  17.088 14.592 17.28 14.616 ;
    END
  END o[122]
  PIN o[123]
    DIRECTION OUTPUT ;
    USE SIGNAL ;
    PORT
      LAYER M4 ;
        RECT  17.088 14.688 17.28 14.712 ;
    END
  END o[123]
  PIN o[124]
    DIRECTION OUTPUT ;
    USE SIGNAL ;
    PORT
      LAYER M4 ;
        RECT  17.088 14.784 17.28 14.808 ;
    END
  END o[124]
  PIN o[125]
    DIRECTION OUTPUT ;
    USE SIGNAL ;
    PORT
      LAYER M4 ;
        RECT  17.088 14.88 17.28 14.904 ;
    END
  END o[125]
  PIN o[126]
    DIRECTION OUTPUT ;
    USE SIGNAL ;
    PORT
      LAYER M4 ;
        RECT  17.088 14.976 17.28 15 ;
    END
  END o[126]
  PIN o[127]
    DIRECTION OUTPUT ;
    USE SIGNAL ;
    PORT
      LAYER M4 ;
        RECT  17.088 15.12 17.28 15.144 ;
    END
  END o[127]
  PIN o[128]
    DIRECTION OUTPUT ;
    USE SIGNAL ;
    PORT
      LAYER M4 ;
        RECT  17.088 15.216 17.28 15.24 ;
    END
  END o[128]
  PIN o[129]
    DIRECTION OUTPUT ;
    USE SIGNAL ;
    PORT
      LAYER M4 ;
        RECT  17.088 15.312 17.28 15.336 ;
    END
  END o[129]
  PIN o[12]
    DIRECTION OUTPUT ;
    USE SIGNAL ;
    PORT
      LAYER M4 ;
        RECT  17.088 3.456 17.28 3.48 ;
    END
  END o[12]
  PIN o[130]
    DIRECTION OUTPUT ;
    USE SIGNAL ;
    PORT
      LAYER M4 ;
        RECT  17.088 15.408 17.28 15.432 ;
    END
  END o[130]
  PIN o[131]
    DIRECTION OUTPUT ;
    USE SIGNAL ;
    PORT
      LAYER M4 ;
        RECT  17.088 15.504 17.28 15.528 ;
    END
  END o[131]
  PIN o[132]
    DIRECTION OUTPUT ;
    USE SIGNAL ;
    PORT
      LAYER M4 ;
        RECT  17.088 15.6 17.28 15.624 ;
    END
  END o[132]
  PIN o[133]
    DIRECTION OUTPUT ;
    USE SIGNAL ;
    PORT
      LAYER M4 ;
        RECT  17.088 15.696 17.28 15.72 ;
    END
  END o[133]
  PIN o[134]
    DIRECTION OUTPUT ;
    USE SIGNAL ;
    PORT
      LAYER M4 ;
        RECT  17.088 15.792 17.28 15.816 ;
    END
  END o[134]
  PIN o[135]
    DIRECTION OUTPUT ;
    USE SIGNAL ;
    PORT
      LAYER M4 ;
        RECT  17.088 15.888 17.28 15.912 ;
    END
  END o[135]
  PIN o[136]
    DIRECTION OUTPUT ;
    USE SIGNAL ;
    PORT
      LAYER M4 ;
        RECT  17.088 16.032 17.28 16.056 ;
    END
  END o[136]
  PIN o[137]
    DIRECTION OUTPUT ;
    USE SIGNAL ;
    PORT
      LAYER M4 ;
        RECT  17.088 16.128 17.28 16.152 ;
    END
  END o[137]
  PIN o[138]
    DIRECTION OUTPUT ;
    USE SIGNAL ;
    PORT
      LAYER M4 ;
        RECT  17.088 16.32 17.28 16.344 ;
    END
  END o[138]
  PIN o[139]
    DIRECTION OUTPUT ;
    USE SIGNAL ;
    PORT
      LAYER M4 ;
        RECT  17.088 16.416 17.28 16.44 ;
    END
  END o[139]
  PIN o[13]
    DIRECTION OUTPUT ;
    USE SIGNAL ;
    PORT
      LAYER M4 ;
        RECT  17.088 3.552 17.28 3.576 ;
    END
  END o[13]
  PIN o[140]
    DIRECTION OUTPUT ;
    USE SIGNAL ;
    PORT
      LAYER M4 ;
        RECT  17.088 16.512 17.28 16.536 ;
    END
  END o[140]
  PIN o[141]
    DIRECTION OUTPUT ;
    USE SIGNAL ;
    PORT
      LAYER M4 ;
        RECT  17.088 16.608 17.28 16.632 ;
    END
  END o[141]
  PIN o[142]
    DIRECTION OUTPUT ;
    USE SIGNAL ;
    PORT
      LAYER M4 ;
        RECT  17.088 16.704 17.28 16.728 ;
    END
  END o[142]
  PIN o[143]
    DIRECTION OUTPUT ;
    USE SIGNAL ;
    PORT
      LAYER M4 ;
        RECT  17.088 16.8 17.28 16.824 ;
    END
  END o[143]
  PIN o[144]
    DIRECTION OUTPUT ;
    USE SIGNAL ;
    PORT
      LAYER M4 ;
        RECT  17.088 16.944 17.28 16.968 ;
    END
  END o[144]
  PIN o[145]
    DIRECTION OUTPUT ;
    USE SIGNAL ;
    PORT
      LAYER M4 ;
        RECT  17.088 17.04 17.28 17.064 ;
    END
  END o[145]
  PIN o[146]
    DIRECTION OUTPUT ;
    USE SIGNAL ;
    PORT
      LAYER M4 ;
        RECT  17.088 17.136 17.28 17.16 ;
    END
  END o[146]
  PIN o[147]
    DIRECTION OUTPUT ;
    USE SIGNAL ;
    PORT
      LAYER M4 ;
        RECT  17.088 17.232 17.28 17.256 ;
    END
  END o[147]
  PIN o[148]
    DIRECTION OUTPUT ;
    USE SIGNAL ;
    PORT
      LAYER M4 ;
        RECT  17.088 17.328 17.28 17.352 ;
    END
  END o[148]
  PIN o[149]
    DIRECTION OUTPUT ;
    USE SIGNAL ;
    PORT
      LAYER M4 ;
        RECT  17.088 17.424 17.28 17.448 ;
    END
  END o[149]
  PIN o[14]
    DIRECTION OUTPUT ;
    USE SIGNAL ;
    PORT
      LAYER M4 ;
        RECT  17.088 3.648 17.28 3.672 ;
    END
  END o[14]
  PIN o[150]
    DIRECTION OUTPUT ;
    USE SIGNAL ;
    PORT
      LAYER M4 ;
        RECT  17.088 17.52 17.28 17.544 ;
    END
  END o[150]
  PIN o[151]
    DIRECTION OUTPUT ;
    USE SIGNAL ;
    PORT
      LAYER M4 ;
        RECT  17.088 17.616 17.28 17.64 ;
    END
  END o[151]
  PIN o[152]
    DIRECTION OUTPUT ;
    USE SIGNAL ;
    PORT
      LAYER M4 ;
        RECT  17.088 17.712 17.28 17.736 ;
    END
  END o[152]
  PIN o[153]
    DIRECTION OUTPUT ;
    USE SIGNAL ;
    PORT
      LAYER M4 ;
        RECT  17.088 17.856 17.28 17.88 ;
    END
  END o[153]
  PIN o[154]
    DIRECTION OUTPUT ;
    USE SIGNAL ;
    PORT
      LAYER M4 ;
        RECT  17.088 17.952 17.28 17.976 ;
    END
  END o[154]
  PIN o[155]
    DIRECTION OUTPUT ;
    USE SIGNAL ;
    PORT
      LAYER M4 ;
        RECT  17.088 18.048 17.28 18.072 ;
    END
  END o[155]
  PIN o[156]
    DIRECTION OUTPUT ;
    USE SIGNAL ;
    PORT
      LAYER M4 ;
        RECT  17.088 18.144 17.28 18.168 ;
    END
  END o[156]
  PIN o[157]
    DIRECTION OUTPUT ;
    USE SIGNAL ;
    PORT
      LAYER M4 ;
        RECT  17.088 18.24 17.28 18.264 ;
    END
  END o[157]
  PIN o[158]
    DIRECTION OUTPUT ;
    USE SIGNAL ;
    PORT
      LAYER M4 ;
        RECT  17.088 18.336 17.28 18.36 ;
    END
  END o[158]
  PIN o[159]
    DIRECTION OUTPUT ;
    USE SIGNAL ;
    PORT
      LAYER M4 ;
        RECT  17.088 18.432 17.28 18.456 ;
    END
  END o[159]
  PIN o[15]
    DIRECTION OUTPUT ;
    USE SIGNAL ;
    PORT
      LAYER M4 ;
        RECT  17.088 3.744 17.28 3.768 ;
    END
  END o[15]
  PIN o[160]
    DIRECTION OUTPUT ;
    USE SIGNAL ;
    PORT
      LAYER M4 ;
        RECT  17.088 18.528 17.28 18.552 ;
    END
  END o[160]
  PIN o[161]
    DIRECTION OUTPUT ;
    USE SIGNAL ;
    PORT
      LAYER M4 ;
        RECT  17.088 18.624 17.28 18.648 ;
    END
  END o[161]
  PIN o[162]
    DIRECTION OUTPUT ;
    USE SIGNAL ;
    PORT
      LAYER M4 ;
        RECT  17.088 18.768 17.28 18.792 ;
    END
  END o[162]
  PIN o[163]
    DIRECTION OUTPUT ;
    USE SIGNAL ;
    PORT
      LAYER M4 ;
        RECT  17.088 18.864 17.28 18.888 ;
    END
  END o[163]
  PIN o[164]
    DIRECTION OUTPUT ;
    USE SIGNAL ;
    PORT
      LAYER M4 ;
        RECT  17.088 18.96 17.28 18.984 ;
    END
  END o[164]
  PIN o[165]
    DIRECTION OUTPUT ;
    USE SIGNAL ;
    PORT
      LAYER M4 ;
        RECT  17.088 19.056 17.28 19.08 ;
    END
  END o[165]
  PIN o[166]
    DIRECTION OUTPUT ;
    USE SIGNAL ;
    PORT
      LAYER M4 ;
        RECT  17.088 19.152 17.28 19.176 ;
    END
  END o[166]
  PIN o[167]
    DIRECTION OUTPUT ;
    USE SIGNAL ;
    PORT
      LAYER M4 ;
        RECT  17.088 19.248 17.28 19.272 ;
    END
  END o[167]
  PIN o[168]
    DIRECTION OUTPUT ;
    USE SIGNAL ;
    PORT
      LAYER M4 ;
        RECT  17.088 19.344 17.28 19.368 ;
    END
  END o[168]
  PIN o[169]
    DIRECTION OUTPUT ;
    USE SIGNAL ;
    PORT
      LAYER M4 ;
        RECT  17.088 19.44 17.28 19.464 ;
    END
  END o[169]
  PIN o[16]
    DIRECTION OUTPUT ;
    USE SIGNAL ;
    PORT
      LAYER M4 ;
        RECT  17.088 3.84 17.28 3.864 ;
    END
  END o[16]
  PIN o[170]
    DIRECTION OUTPUT ;
    USE SIGNAL ;
    PORT
      LAYER M4 ;
        RECT  17.088 19.536 17.28 19.56 ;
    END
  END o[170]
  PIN o[171]
    DIRECTION OUTPUT ;
    USE SIGNAL ;
    PORT
      LAYER M4 ;
        RECT  17.088 19.68 17.28 19.704 ;
    END
  END o[171]
  PIN o[172]
    DIRECTION OUTPUT ;
    USE SIGNAL ;
    PORT
      LAYER M4 ;
        RECT  17.088 19.776 17.28 19.8 ;
    END
  END o[172]
  PIN o[173]
    DIRECTION OUTPUT ;
    USE SIGNAL ;
    PORT
      LAYER M4 ;
        RECT  17.088 19.872 17.28 19.896 ;
    END
  END o[173]
  PIN o[174]
    DIRECTION OUTPUT ;
    USE SIGNAL ;
    PORT
      LAYER M4 ;
        RECT  17.088 19.968 17.28 19.992 ;
    END
  END o[174]
  PIN o[175]
    DIRECTION OUTPUT ;
    USE SIGNAL ;
    PORT
      LAYER M4 ;
        RECT  17.088 20.064 17.28 20.088 ;
    END
  END o[175]
  PIN o[176]
    DIRECTION OUTPUT ;
    USE SIGNAL ;
    PORT
      LAYER M4 ;
        RECT  17.088 20.16 17.28 20.184 ;
    END
  END o[176]
  PIN o[177]
    DIRECTION OUTPUT ;
    USE SIGNAL ;
    PORT
      LAYER M4 ;
        RECT  17.088 20.256 17.28 20.28 ;
    END
  END o[177]
  PIN o[178]
    DIRECTION OUTPUT ;
    USE SIGNAL ;
    PORT
      LAYER M4 ;
        RECT  17.088 20.352 17.28 20.376 ;
    END
  END o[178]
  PIN o[179]
    DIRECTION OUTPUT ;
    USE SIGNAL ;
    PORT
      LAYER M4 ;
        RECT  17.088 20.448 17.28 20.472 ;
    END
  END o[179]
  PIN o[17]
    DIRECTION OUTPUT ;
    USE SIGNAL ;
    PORT
      LAYER M4 ;
        RECT  17.088 3.936 17.28 3.96 ;
    END
  END o[17]
  PIN o[180]
    DIRECTION OUTPUT ;
    USE SIGNAL ;
    PORT
      LAYER M4 ;
        RECT  17.088 20.592 17.28 20.616 ;
    END
  END o[180]
  PIN o[181]
    DIRECTION OUTPUT ;
    USE SIGNAL ;
    PORT
      LAYER M4 ;
        RECT  17.088 20.688 17.28 20.712 ;
    END
  END o[181]
  PIN o[182]
    DIRECTION OUTPUT ;
    USE SIGNAL ;
    PORT
      LAYER M4 ;
        RECT  17.088 20.784 17.28 20.808 ;
    END
  END o[182]
  PIN o[183]
    DIRECTION OUTPUT ;
    USE SIGNAL ;
    PORT
      LAYER M4 ;
        RECT  17.088 20.88 17.28 20.904 ;
    END
  END o[183]
  PIN o[184]
    DIRECTION OUTPUT ;
    USE SIGNAL ;
    PORT
      LAYER M4 ;
        RECT  17.088 20.976 17.28 21 ;
    END
  END o[184]
  PIN o[185]
    DIRECTION OUTPUT ;
    USE SIGNAL ;
    PORT
      LAYER M4 ;
        RECT  17.088 21.072 17.28 21.096 ;
    END
  END o[185]
  PIN o[186]
    DIRECTION OUTPUT ;
    USE SIGNAL ;
    PORT
      LAYER M4 ;
        RECT  17.088 21.168 17.28 21.192 ;
    END
  END o[186]
  PIN o[187]
    DIRECTION OUTPUT ;
    USE SIGNAL ;
    PORT
      LAYER M4 ;
        RECT  17.088 21.264 17.28 21.288 ;
    END
  END o[187]
  PIN o[188]
    DIRECTION OUTPUT ;
    USE SIGNAL ;
    PORT
      LAYER M4 ;
        RECT  17.088 21.36 17.28 21.384 ;
    END
  END o[188]
  PIN o[189]
    DIRECTION OUTPUT ;
    USE SIGNAL ;
    PORT
      LAYER M4 ;
        RECT  17.088 21.504 17.28 21.528 ;
    END
  END o[189]
  PIN o[18]
    DIRECTION OUTPUT ;
    USE SIGNAL ;
    PORT
      LAYER M4 ;
        RECT  17.088 4.032 17.28 4.056 ;
    END
  END o[18]
  PIN o[190]
    DIRECTION OUTPUT ;
    USE SIGNAL ;
    PORT
      LAYER M4 ;
        RECT  17.088 21.6 17.28 21.624 ;
    END
  END o[190]
  PIN o[191]
    DIRECTION OUTPUT ;
    USE SIGNAL ;
    PORT
      LAYER M4 ;
        RECT  17.088 21.696 17.28 21.72 ;
    END
  END o[191]
  PIN o[192]
    DIRECTION OUTPUT ;
    USE SIGNAL ;
    PORT
      LAYER M4 ;
        RECT  17.088 21.792 17.28 21.816 ;
    END
  END o[192]
  PIN o[193]
    DIRECTION OUTPUT ;
    USE SIGNAL ;
    PORT
      LAYER M4 ;
        RECT  17.088 21.888 17.28 21.912 ;
    END
  END o[193]
  PIN o[194]
    DIRECTION OUTPUT ;
    USE SIGNAL ;
    PORT
      LAYER M4 ;
        RECT  17.088 21.984 17.28 22.008 ;
    END
  END o[194]
  PIN o[195]
    DIRECTION OUTPUT ;
    USE SIGNAL ;
    PORT
      LAYER M4 ;
        RECT  17.088 22.08 17.28 22.104 ;
    END
  END o[195]
  PIN o[196]
    DIRECTION OUTPUT ;
    USE SIGNAL ;
    PORT
      LAYER M4 ;
        RECT  17.088 22.176 17.28 22.2 ;
    END
  END o[196]
  PIN o[197]
    DIRECTION OUTPUT ;
    USE SIGNAL ;
    PORT
      LAYER M4 ;
        RECT  17.088 22.272 17.28 22.296 ;
    END
  END o[197]
  PIN o[198]
    DIRECTION OUTPUT ;
    USE SIGNAL ;
    PORT
      LAYER M4 ;
        RECT  17.088 22.416 17.28 22.44 ;
    END
  END o[198]
  PIN o[199]
    DIRECTION OUTPUT ;
    USE SIGNAL ;
    PORT
      LAYER M4 ;
        RECT  17.088 22.512 17.28 22.536 ;
    END
  END o[199]
  PIN o[19]
    DIRECTION OUTPUT ;
    USE SIGNAL ;
    PORT
      LAYER M4 ;
        RECT  17.088 4.128 17.28 4.152 ;
    END
  END o[19]
  PIN o[1]
    DIRECTION OUTPUT ;
    USE SIGNAL ;
    PORT
      LAYER M4 ;
        RECT  17.088 2.304 17.28 2.328 ;
    END
  END o[1]
  PIN o[200]
    DIRECTION OUTPUT ;
    USE SIGNAL ;
    PORT
      LAYER M4 ;
        RECT  17.088 22.608 17.28 22.632 ;
    END
  END o[200]
  PIN o[201]
    DIRECTION OUTPUT ;
    USE SIGNAL ;
    PORT
      LAYER M4 ;
        RECT  17.088 22.704 17.28 22.728 ;
    END
  END o[201]
  PIN o[202]
    DIRECTION OUTPUT ;
    USE SIGNAL ;
    PORT
      LAYER M4 ;
        RECT  17.088 22.8 17.28 22.824 ;
    END
  END o[202]
  PIN o[203]
    DIRECTION OUTPUT ;
    USE SIGNAL ;
    PORT
      LAYER M4 ;
        RECT  17.088 22.896 17.28 22.92 ;
    END
  END o[203]
  PIN o[204]
    DIRECTION OUTPUT ;
    USE SIGNAL ;
    PORT
      LAYER M4 ;
        RECT  17.088 22.992 17.28 23.016 ;
    END
  END o[204]
  PIN o[205]
    DIRECTION OUTPUT ;
    USE SIGNAL ;
    PORT
      LAYER M4 ;
        RECT  17.088 23.088 17.28 23.112 ;
    END
  END o[205]
  PIN o[206]
    DIRECTION OUTPUT ;
    USE SIGNAL ;
    PORT
      LAYER M4 ;
        RECT  17.088 23.184 17.28 23.208 ;
    END
  END o[206]
  PIN o[207]
    DIRECTION OUTPUT ;
    USE SIGNAL ;
    PORT
      LAYER M4 ;
        RECT  17.088 23.328 17.28 23.352 ;
    END
  END o[207]
  PIN o[208]
    DIRECTION OUTPUT ;
    USE SIGNAL ;
    PORT
      LAYER M4 ;
        RECT  17.088 23.424 17.28 23.448 ;
    END
  END o[208]
  PIN o[209]
    DIRECTION OUTPUT ;
    USE SIGNAL ;
    PORT
      LAYER M4 ;
        RECT  17.088 23.52 17.28 23.544 ;
    END
  END o[209]
  PIN o[20]
    DIRECTION OUTPUT ;
    USE SIGNAL ;
    PORT
      LAYER M4 ;
        RECT  17.088 4.272 17.28 4.296 ;
    END
  END o[20]
  PIN o[210]
    DIRECTION OUTPUT ;
    USE SIGNAL ;
    PORT
      LAYER M4 ;
        RECT  17.088 23.616 17.28 23.64 ;
    END
  END o[210]
  PIN o[211]
    DIRECTION OUTPUT ;
    USE SIGNAL ;
    PORT
      LAYER M4 ;
        RECT  17.088 23.712 17.28 23.736 ;
    END
  END o[211]
  PIN o[212]
    DIRECTION OUTPUT ;
    USE SIGNAL ;
    PORT
      LAYER M4 ;
        RECT  17.088 23.808 17.28 23.832 ;
    END
  END o[212]
  PIN o[213]
    DIRECTION OUTPUT ;
    USE SIGNAL ;
    PORT
      LAYER M4 ;
        RECT  17.088 23.904 17.28 23.928 ;
    END
  END o[213]
  PIN o[214]
    DIRECTION OUTPUT ;
    USE SIGNAL ;
    PORT
      LAYER M4 ;
        RECT  17.088 24 17.28 24.024 ;
    END
  END o[214]
  PIN o[215]
    DIRECTION OUTPUT ;
    USE SIGNAL ;
    PORT
      LAYER M4 ;
        RECT  17.088 24.096 17.28 24.12 ;
    END
  END o[215]
  PIN o[216]
    DIRECTION OUTPUT ;
    USE SIGNAL ;
    PORT
      LAYER M4 ;
        RECT  17.088 24.24 17.28 24.264 ;
    END
  END o[216]
  PIN o[217]
    DIRECTION OUTPUT ;
    USE SIGNAL ;
    PORT
      LAYER M4 ;
        RECT  17.088 24.336 17.28 24.36 ;
    END
  END o[217]
  PIN o[218]
    DIRECTION OUTPUT ;
    USE SIGNAL ;
    PORT
      LAYER M4 ;
        RECT  17.088 24.432 17.28 24.456 ;
    END
  END o[218]
  PIN o[219]
    DIRECTION OUTPUT ;
    USE SIGNAL ;
    PORT
      LAYER M4 ;
        RECT  17.088 24.528 17.28 24.552 ;
    END
  END o[219]
  PIN o[21]
    DIRECTION OUTPUT ;
    USE SIGNAL ;
    PORT
      LAYER M4 ;
        RECT  17.088 4.368 17.28 4.392 ;
    END
  END o[21]
  PIN o[220]
    DIRECTION OUTPUT ;
    USE SIGNAL ;
    PORT
      LAYER M4 ;
        RECT  17.088 24.624 17.28 24.648 ;
    END
  END o[220]
  PIN o[221]
    DIRECTION OUTPUT ;
    USE SIGNAL ;
    PORT
      LAYER M4 ;
        RECT  17.088 24.72 17.28 24.744 ;
    END
  END o[221]
  PIN o[222]
    DIRECTION OUTPUT ;
    USE SIGNAL ;
    PORT
      LAYER M4 ;
        RECT  17.088 24.816 17.28 24.84 ;
    END
  END o[222]
  PIN o[223]
    DIRECTION OUTPUT ;
    USE SIGNAL ;
    PORT
      LAYER M4 ;
        RECT  17.088 24.912 17.28 24.936 ;
    END
  END o[223]
  PIN o[224]
    DIRECTION OUTPUT ;
    USE SIGNAL ;
    PORT
      LAYER M4 ;
        RECT  17.088 25.008 17.28 25.032 ;
    END
  END o[224]
  PIN o[225]
    DIRECTION OUTPUT ;
    USE SIGNAL ;
    PORT
      LAYER M4 ;
        RECT  17.088 25.152 17.28 25.176 ;
    END
  END o[225]
  PIN o[226]
    DIRECTION OUTPUT ;
    USE SIGNAL ;
    PORT
      LAYER M4 ;
        RECT  17.088 25.248 17.28 25.272 ;
    END
  END o[226]
  PIN o[227]
    DIRECTION OUTPUT ;
    USE SIGNAL ;
    PORT
      LAYER M4 ;
        RECT  17.088 25.344 17.28 25.368 ;
    END
  END o[227]
  PIN o[228]
    DIRECTION OUTPUT ;
    USE SIGNAL ;
    PORT
      LAYER M4 ;
        RECT  17.088 25.44 17.28 25.464 ;
    END
  END o[228]
  PIN o[229]
    DIRECTION OUTPUT ;
    USE SIGNAL ;
    PORT
      LAYER M4 ;
        RECT  17.088 25.536 17.28 25.56 ;
    END
  END o[229]
  PIN o[22]
    DIRECTION OUTPUT ;
    USE SIGNAL ;
    PORT
      LAYER M4 ;
        RECT  17.088 4.464 17.28 4.488 ;
    END
  END o[22]
  PIN o[230]
    DIRECTION OUTPUT ;
    USE SIGNAL ;
    PORT
      LAYER M4 ;
        RECT  17.088 25.632 17.28 25.656 ;
    END
  END o[230]
  PIN o[231]
    DIRECTION OUTPUT ;
    USE SIGNAL ;
    PORT
      LAYER M4 ;
        RECT  17.088 25.728 17.28 25.752 ;
    END
  END o[231]
  PIN o[232]
    DIRECTION OUTPUT ;
    USE SIGNAL ;
    PORT
      LAYER M4 ;
        RECT  17.088 25.824 17.28 25.848 ;
    END
  END o[232]
  PIN o[233]
    DIRECTION OUTPUT ;
    USE SIGNAL ;
    PORT
      LAYER M4 ;
        RECT  17.088 25.92 17.28 25.944 ;
    END
  END o[233]
  PIN o[234]
    DIRECTION OUTPUT ;
    USE SIGNAL ;
    PORT
      LAYER M4 ;
        RECT  17.088 26.064 17.28 26.088 ;
    END
  END o[234]
  PIN o[235]
    DIRECTION OUTPUT ;
    USE SIGNAL ;
    PORT
      LAYER M4 ;
        RECT  17.088 26.16 17.28 26.184 ;
    END
  END o[235]
  PIN o[236]
    DIRECTION OUTPUT ;
    USE SIGNAL ;
    PORT
      LAYER M4 ;
        RECT  17.088 26.256 17.28 26.28 ;
    END
  END o[236]
  PIN o[237]
    DIRECTION OUTPUT ;
    USE SIGNAL ;
    PORT
      LAYER M4 ;
        RECT  17.088 26.352 17.28 26.376 ;
    END
  END o[237]
  PIN o[238]
    DIRECTION OUTPUT ;
    USE SIGNAL ;
    PORT
      LAYER M4 ;
        RECT  17.088 26.448 17.28 26.472 ;
    END
  END o[238]
  PIN o[239]
    DIRECTION OUTPUT ;
    USE SIGNAL ;
    PORT
      LAYER M4 ;
        RECT  17.088 26.544 17.28 26.568 ;
    END
  END o[239]
  PIN o[23]
    DIRECTION OUTPUT ;
    USE SIGNAL ;
    PORT
      LAYER M4 ;
        RECT  17.088 4.56 17.28 4.584 ;
    END
  END o[23]
  PIN o[240]
    DIRECTION OUTPUT ;
    USE SIGNAL ;
    PORT
      LAYER M4 ;
        RECT  17.088 26.64 17.28 26.664 ;
    END
  END o[240]
  PIN o[241]
    DIRECTION OUTPUT ;
    USE SIGNAL ;
    PORT
      LAYER M4 ;
        RECT  17.088 26.736 17.28 26.76 ;
    END
  END o[241]
  PIN o[242]
    DIRECTION OUTPUT ;
    USE SIGNAL ;
    PORT
      LAYER M4 ;
        RECT  17.088 26.88 17.28 26.904 ;
    END
  END o[242]
  PIN o[243]
    DIRECTION OUTPUT ;
    USE SIGNAL ;
    PORT
      LAYER M4 ;
        RECT  17.088 26.976 17.28 27 ;
    END
  END o[243]
  PIN o[244]
    DIRECTION OUTPUT ;
    USE SIGNAL ;
    PORT
      LAYER M4 ;
        RECT  17.088 27.072 17.28 27.096 ;
    END
  END o[244]
  PIN o[245]
    DIRECTION OUTPUT ;
    USE SIGNAL ;
    PORT
      LAYER M4 ;
        RECT  17.088 27.168 17.28 27.192 ;
    END
  END o[245]
  PIN o[246]
    DIRECTION OUTPUT ;
    USE SIGNAL ;
    PORT
      LAYER M4 ;
        RECT  17.088 27.264 17.28 27.288 ;
    END
  END o[246]
  PIN o[247]
    DIRECTION OUTPUT ;
    USE SIGNAL ;
    PORT
      LAYER M4 ;
        RECT  17.088 27.36 17.28 27.384 ;
    END
  END o[247]
  PIN o[248]
    DIRECTION OUTPUT ;
    USE SIGNAL ;
    PORT
      LAYER M4 ;
        RECT  17.088 27.456 17.28 27.48 ;
    END
  END o[248]
  PIN o[249]
    DIRECTION OUTPUT ;
    USE SIGNAL ;
    PORT
      LAYER M4 ;
        RECT  17.088 27.552 17.28 27.576 ;
    END
  END o[249]
  PIN o[24]
    DIRECTION OUTPUT ;
    USE SIGNAL ;
    PORT
      LAYER M4 ;
        RECT  17.088 4.656 17.28 4.68 ;
    END
  END o[24]
  PIN o[250]
    DIRECTION OUTPUT ;
    USE SIGNAL ;
    PORT
      LAYER M4 ;
        RECT  17.088 27.648 17.28 27.672 ;
    END
  END o[250]
  PIN o[251]
    DIRECTION OUTPUT ;
    USE SIGNAL ;
    PORT
      LAYER M4 ;
        RECT  17.088 27.792 17.28 27.816 ;
    END
  END o[251]
  PIN o[252]
    DIRECTION OUTPUT ;
    USE SIGNAL ;
    PORT
      LAYER M4 ;
        RECT  17.088 27.888 17.28 27.912 ;
    END
  END o[252]
  PIN o[253]
    DIRECTION OUTPUT ;
    USE SIGNAL ;
    PORT
      LAYER M4 ;
        RECT  17.088 27.984 17.28 28.008 ;
    END
  END o[253]
  PIN o[254]
    DIRECTION OUTPUT ;
    USE SIGNAL ;
    PORT
      LAYER M4 ;
        RECT  17.088 28.08 17.28 28.104 ;
    END
  END o[254]
  PIN o[255]
    DIRECTION OUTPUT ;
    USE SIGNAL ;
    PORT
      LAYER M4 ;
        RECT  17.088 28.176 17.28 28.2 ;
    END
  END o[255]
  PIN o[256]
    DIRECTION OUTPUT ;
    USE SIGNAL ;
    PORT
      LAYER M4 ;
        RECT  17.088 28.272 17.28 28.296 ;
    END
  END o[256]
  PIN o[257]
    DIRECTION OUTPUT ;
    USE SIGNAL ;
    PORT
      LAYER M4 ;
        RECT  17.088 28.368 17.28 28.392 ;
    END
  END o[257]
  PIN o[258]
    DIRECTION OUTPUT ;
    USE SIGNAL ;
    PORT
      LAYER M4 ;
        RECT  17.088 28.464 17.28 28.488 ;
    END
  END o[258]
  PIN o[259]
    DIRECTION OUTPUT ;
    USE SIGNAL ;
    PORT
      LAYER M4 ;
        RECT  17.088 28.56 17.28 28.584 ;
    END
  END o[259]
  PIN o[25]
    DIRECTION OUTPUT ;
    USE SIGNAL ;
    PORT
      LAYER M4 ;
        RECT  17.088 4.752 17.28 4.776 ;
    END
  END o[25]
  PIN o[260]
    DIRECTION OUTPUT ;
    USE SIGNAL ;
    PORT
      LAYER M4 ;
        RECT  17.088 28.704 17.28 28.728 ;
    END
  END o[260]
  PIN o[261]
    DIRECTION OUTPUT ;
    USE SIGNAL ;
    PORT
      LAYER M4 ;
        RECT  17.088 28.8 17.28 28.824 ;
    END
  END o[261]
  PIN o[262]
    DIRECTION OUTPUT ;
    USE SIGNAL ;
    PORT
      LAYER M4 ;
        RECT  17.088 28.896 17.28 28.92 ;
    END
  END o[262]
  PIN o[263]
    DIRECTION OUTPUT ;
    USE SIGNAL ;
    PORT
      LAYER M4 ;
        RECT  17.088 28.992 17.28 29.016 ;
    END
  END o[263]
  PIN o[264]
    DIRECTION OUTPUT ;
    USE SIGNAL ;
    PORT
      LAYER M4 ;
        RECT  17.088 29.088 17.28 29.112 ;
    END
  END o[264]
  PIN o[265]
    DIRECTION OUTPUT ;
    USE SIGNAL ;
    PORT
      LAYER M4 ;
        RECT  17.088 29.184 17.28 29.208 ;
    END
  END o[265]
  PIN o[266]
    DIRECTION OUTPUT ;
    USE SIGNAL ;
    PORT
      LAYER M4 ;
        RECT  17.088 29.28 17.28 29.304 ;
    END
  END o[266]
  PIN o[267]
    DIRECTION OUTPUT ;
    USE SIGNAL ;
    PORT
      LAYER M4 ;
        RECT  17.088 29.376 17.28 29.4 ;
    END
  END o[267]
  PIN o[268]
    DIRECTION OUTPUT ;
    USE SIGNAL ;
    PORT
      LAYER M4 ;
        RECT  17.088 29.472 17.28 29.496 ;
    END
  END o[268]
  PIN o[269]
    DIRECTION OUTPUT ;
    USE SIGNAL ;
    PORT
      LAYER M4 ;
        RECT  17.088 29.616 17.28 29.64 ;
    END
  END o[269]
  PIN o[26]
    DIRECTION OUTPUT ;
    USE SIGNAL ;
    PORT
      LAYER M4 ;
        RECT  17.088 4.848 17.28 4.872 ;
    END
  END o[26]
  PIN o[270]
    DIRECTION OUTPUT ;
    USE SIGNAL ;
    PORT
      LAYER M4 ;
        RECT  17.088 29.712 17.28 29.736 ;
    END
  END o[270]
  PIN o[271]
    DIRECTION OUTPUT ;
    USE SIGNAL ;
    PORT
      LAYER M4 ;
        RECT  17.088 29.808 17.28 29.832 ;
    END
  END o[271]
  PIN o[272]
    DIRECTION OUTPUT ;
    USE SIGNAL ;
    PORT
      LAYER M4 ;
        RECT  17.088 29.904 17.28 29.928 ;
    END
  END o[272]
  PIN o[273]
    DIRECTION OUTPUT ;
    USE SIGNAL ;
    PORT
      LAYER M4 ;
        RECT  17.088 30 17.28 30.024 ;
    END
  END o[273]
  PIN o[274]
    DIRECTION OUTPUT ;
    USE SIGNAL ;
    PORT
      LAYER M4 ;
        RECT  17.088 30.096 17.28 30.12 ;
    END
  END o[274]
  PIN o[275]
    DIRECTION OUTPUT ;
    USE SIGNAL ;
    PORT
      LAYER M4 ;
        RECT  17.088 30.192 17.28 30.216 ;
    END
  END o[275]
  PIN o[27]
    DIRECTION OUTPUT ;
    USE SIGNAL ;
    PORT
      LAYER M4 ;
        RECT  17.088 4.944 17.28 4.968 ;
    END
  END o[27]
  PIN o[28]
    DIRECTION OUTPUT ;
    USE SIGNAL ;
    PORT
      LAYER M4 ;
        RECT  17.088 5.04 17.28 5.064 ;
    END
  END o[28]
  PIN o[29]
    DIRECTION OUTPUT ;
    USE SIGNAL ;
    PORT
      LAYER M4 ;
        RECT  17.088 5.184 17.28 5.208 ;
    END
  END o[29]
  PIN o[2]
    DIRECTION OUTPUT ;
    USE SIGNAL ;
    PORT
      LAYER M4 ;
        RECT  17.088 2.448 17.28 2.472 ;
    END
  END o[2]
  PIN o[30]
    DIRECTION OUTPUT ;
    USE SIGNAL ;
    PORT
      LAYER M4 ;
        RECT  17.088 5.28 17.28 5.304 ;
    END
  END o[30]
  PIN o[31]
    DIRECTION OUTPUT ;
    USE SIGNAL ;
    PORT
      LAYER M4 ;
        RECT  17.088 5.376 17.28 5.4 ;
    END
  END o[31]
  PIN o[32]
    DIRECTION OUTPUT ;
    USE SIGNAL ;
    PORT
      LAYER M4 ;
        RECT  17.088 5.472 17.28 5.496 ;
    END
  END o[32]
  PIN o[33]
    DIRECTION OUTPUT ;
    USE SIGNAL ;
    PORT
      LAYER M4 ;
        RECT  17.088 5.568 17.28 5.592 ;
    END
  END o[33]
  PIN o[34]
    DIRECTION OUTPUT ;
    USE SIGNAL ;
    PORT
      LAYER M4 ;
        RECT  17.088 5.664 17.28 5.688 ;
    END
  END o[34]
  PIN o[35]
    DIRECTION OUTPUT ;
    USE SIGNAL ;
    PORT
      LAYER M4 ;
        RECT  17.088 5.76 17.28 5.784 ;
    END
  END o[35]
  PIN o[36]
    DIRECTION OUTPUT ;
    USE SIGNAL ;
    PORT
      LAYER M4 ;
        RECT  17.088 5.856 17.28 5.88 ;
    END
  END o[36]
  PIN o[37]
    DIRECTION OUTPUT ;
    USE SIGNAL ;
    PORT
      LAYER M4 ;
        RECT  17.088 5.952 17.28 5.976 ;
    END
  END o[37]
  PIN o[38]
    DIRECTION OUTPUT ;
    USE SIGNAL ;
    PORT
      LAYER M4 ;
        RECT  17.088 6.096 17.28 6.12 ;
    END
  END o[38]
  PIN o[39]
    DIRECTION OUTPUT ;
    USE SIGNAL ;
    PORT
      LAYER M4 ;
        RECT  17.088 6.192 17.28 6.216 ;
    END
  END o[39]
  PIN o[3]
    DIRECTION OUTPUT ;
    USE SIGNAL ;
    PORT
      LAYER M4 ;
        RECT  17.088 2.544 17.28 2.568 ;
    END
  END o[3]
  PIN o[40]
    DIRECTION OUTPUT ;
    USE SIGNAL ;
    PORT
      LAYER M4 ;
        RECT  17.088 6.288 17.28 6.312 ;
    END
  END o[40]
  PIN o[41]
    DIRECTION OUTPUT ;
    USE SIGNAL ;
    PORT
      LAYER M4 ;
        RECT  17.088 6.384 17.28 6.408 ;
    END
  END o[41]
  PIN o[42]
    DIRECTION OUTPUT ;
    USE SIGNAL ;
    PORT
      LAYER M4 ;
        RECT  17.088 6.48 17.28 6.504 ;
    END
  END o[42]
  PIN o[43]
    DIRECTION OUTPUT ;
    USE SIGNAL ;
    PORT
      LAYER M4 ;
        RECT  17.088 6.576 17.28 6.6 ;
    END
  END o[43]
  PIN o[44]
    DIRECTION OUTPUT ;
    USE SIGNAL ;
    PORT
      LAYER M4 ;
        RECT  17.088 6.672 17.28 6.696 ;
    END
  END o[44]
  PIN o[45]
    DIRECTION OUTPUT ;
    USE SIGNAL ;
    PORT
      LAYER M4 ;
        RECT  17.088 6.768 17.28 6.792 ;
    END
  END o[45]
  PIN o[46]
    DIRECTION OUTPUT ;
    USE SIGNAL ;
    PORT
      LAYER M4 ;
        RECT  17.088 6.864 17.28 6.888 ;
    END
  END o[46]
  PIN o[47]
    DIRECTION OUTPUT ;
    USE SIGNAL ;
    PORT
      LAYER M4 ;
        RECT  17.088 7.008 17.28 7.032 ;
    END
  END o[47]
  PIN o[48]
    DIRECTION OUTPUT ;
    USE SIGNAL ;
    PORT
      LAYER M4 ;
        RECT  17.088 7.104 17.28 7.128 ;
    END
  END o[48]
  PIN o[49]
    DIRECTION OUTPUT ;
    USE SIGNAL ;
    PORT
      LAYER M4 ;
        RECT  17.088 7.2 17.28 7.224 ;
    END
  END o[49]
  PIN o[4]
    DIRECTION OUTPUT ;
    USE SIGNAL ;
    PORT
      LAYER M4 ;
        RECT  17.088 2.64 17.28 2.664 ;
    END
  END o[4]
  PIN o[50]
    DIRECTION OUTPUT ;
    USE SIGNAL ;
    PORT
      LAYER M4 ;
        RECT  17.088 7.296 17.28 7.32 ;
    END
  END o[50]
  PIN o[51]
    DIRECTION OUTPUT ;
    USE SIGNAL ;
    PORT
      LAYER M4 ;
        RECT  17.088 7.392 17.28 7.416 ;
    END
  END o[51]
  PIN o[52]
    DIRECTION OUTPUT ;
    USE SIGNAL ;
    PORT
      LAYER M4 ;
        RECT  17.088 7.488 17.28 7.512 ;
    END
  END o[52]
  PIN o[53]
    DIRECTION OUTPUT ;
    USE SIGNAL ;
    PORT
      LAYER M4 ;
        RECT  17.088 7.584 17.28 7.608 ;
    END
  END o[53]
  PIN o[54]
    DIRECTION OUTPUT ;
    USE SIGNAL ;
    PORT
      LAYER M4 ;
        RECT  17.088 7.68 17.28 7.704 ;
    END
  END o[54]
  PIN o[55]
    DIRECTION OUTPUT ;
    USE SIGNAL ;
    PORT
      LAYER M4 ;
        RECT  17.088 7.776 17.28 7.8 ;
    END
  END o[55]
  PIN o[56]
    DIRECTION OUTPUT ;
    USE SIGNAL ;
    PORT
      LAYER M4 ;
        RECT  17.088 7.92 17.28 7.944 ;
    END
  END o[56]
  PIN o[57]
    DIRECTION OUTPUT ;
    USE SIGNAL ;
    PORT
      LAYER M4 ;
        RECT  17.088 8.016 17.28 8.04 ;
    END
  END o[57]
  PIN o[58]
    DIRECTION OUTPUT ;
    USE SIGNAL ;
    PORT
      LAYER M4 ;
        RECT  17.088 8.112 17.28 8.136 ;
    END
  END o[58]
  PIN o[59]
    DIRECTION OUTPUT ;
    USE SIGNAL ;
    PORT
      LAYER M4 ;
        RECT  17.088 8.208 17.28 8.232 ;
    END
  END o[59]
  PIN o[5]
    DIRECTION OUTPUT ;
    USE SIGNAL ;
    PORT
      LAYER M4 ;
        RECT  17.088 2.736 17.28 2.76 ;
    END
  END o[5]
  PIN o[60]
    DIRECTION OUTPUT ;
    USE SIGNAL ;
    PORT
      LAYER M4 ;
        RECT  17.088 8.304 17.28 8.328 ;
    END
  END o[60]
  PIN o[61]
    DIRECTION OUTPUT ;
    USE SIGNAL ;
    PORT
      LAYER M4 ;
        RECT  17.088 8.4 17.28 8.424 ;
    END
  END o[61]
  PIN o[62]
    DIRECTION OUTPUT ;
    USE SIGNAL ;
    PORT
      LAYER M4 ;
        RECT  17.088 8.496 17.28 8.52 ;
    END
  END o[62]
  PIN o[63]
    DIRECTION OUTPUT ;
    USE SIGNAL ;
    PORT
      LAYER M4 ;
        RECT  17.088 8.592 17.28 8.616 ;
    END
  END o[63]
  PIN o[64]
    DIRECTION OUTPUT ;
    USE SIGNAL ;
    PORT
      LAYER M4 ;
        RECT  17.088 8.688 17.28 8.712 ;
    END
  END o[64]
  PIN o[65]
    DIRECTION OUTPUT ;
    USE SIGNAL ;
    PORT
      LAYER M4 ;
        RECT  17.088 8.832 17.28 8.856 ;
    END
  END o[65]
  PIN o[66]
    DIRECTION OUTPUT ;
    USE SIGNAL ;
    PORT
      LAYER M4 ;
        RECT  17.088 8.928 17.28 8.952 ;
    END
  END o[66]
  PIN o[67]
    DIRECTION OUTPUT ;
    USE SIGNAL ;
    PORT
      LAYER M4 ;
        RECT  17.088 9.024 17.28 9.048 ;
    END
  END o[67]
  PIN o[68]
    DIRECTION OUTPUT ;
    USE SIGNAL ;
    PORT
      LAYER M4 ;
        RECT  17.088 9.12 17.28 9.144 ;
    END
  END o[68]
  PIN o[69]
    DIRECTION OUTPUT ;
    USE SIGNAL ;
    PORT
      LAYER M4 ;
        RECT  17.088 9.216 17.28 9.24 ;
    END
  END o[69]
  PIN o[6]
    DIRECTION OUTPUT ;
    USE SIGNAL ;
    PORT
      LAYER M4 ;
        RECT  17.088 2.832 17.28 2.856 ;
    END
  END o[6]
  PIN o[70]
    DIRECTION OUTPUT ;
    USE SIGNAL ;
    PORT
      LAYER M4 ;
        RECT  17.088 9.312 17.28 9.336 ;
    END
  END o[70]
  PIN o[71]
    DIRECTION OUTPUT ;
    USE SIGNAL ;
    PORT
      LAYER M4 ;
        RECT  17.088 9.408 17.28 9.432 ;
    END
  END o[71]
  PIN o[72]
    DIRECTION OUTPUT ;
    USE SIGNAL ;
    PORT
      LAYER M4 ;
        RECT  17.088 9.504 17.28 9.528 ;
    END
  END o[72]
  PIN o[73]
    DIRECTION OUTPUT ;
    USE SIGNAL ;
    PORT
      LAYER M4 ;
        RECT  17.088 9.6 17.28 9.624 ;
    END
  END o[73]
  PIN o[74]
    DIRECTION OUTPUT ;
    USE SIGNAL ;
    PORT
      LAYER M4 ;
        RECT  17.088 9.744 17.28 9.768 ;
    END
  END o[74]
  PIN o[75]
    DIRECTION OUTPUT ;
    USE SIGNAL ;
    PORT
      LAYER M4 ;
        RECT  17.088 9.84 17.28 9.864 ;
    END
  END o[75]
  PIN o[76]
    DIRECTION OUTPUT ;
    USE SIGNAL ;
    PORT
      LAYER M4 ;
        RECT  17.088 9.936 17.28 9.96 ;
    END
  END o[76]
  PIN o[77]
    DIRECTION OUTPUT ;
    USE SIGNAL ;
    PORT
      LAYER M4 ;
        RECT  17.088 10.032 17.28 10.056 ;
    END
  END o[77]
  PIN o[78]
    DIRECTION OUTPUT ;
    USE SIGNAL ;
    PORT
      LAYER M4 ;
        RECT  17.088 10.128 17.28 10.152 ;
    END
  END o[78]
  PIN o[79]
    DIRECTION OUTPUT ;
    USE SIGNAL ;
    PORT
      LAYER M4 ;
        RECT  17.088 10.224 17.28 10.248 ;
    END
  END o[79]
  PIN o[7]
    DIRECTION OUTPUT ;
    USE SIGNAL ;
    PORT
      LAYER M4 ;
        RECT  17.088 2.928 17.28 2.952 ;
    END
  END o[7]
  PIN o[80]
    DIRECTION OUTPUT ;
    USE SIGNAL ;
    PORT
      LAYER M4 ;
        RECT  17.088 10.32 17.28 10.344 ;
    END
  END o[80]
  PIN o[81]
    DIRECTION OUTPUT ;
    USE SIGNAL ;
    PORT
      LAYER M4 ;
        RECT  17.088 10.416 17.28 10.44 ;
    END
  END o[81]
  PIN o[82]
    DIRECTION OUTPUT ;
    USE SIGNAL ;
    PORT
      LAYER M4 ;
        RECT  17.088 10.512 17.28 10.536 ;
    END
  END o[82]
  PIN o[83]
    DIRECTION OUTPUT ;
    USE SIGNAL ;
    PORT
      LAYER M4 ;
        RECT  17.088 10.656 17.28 10.68 ;
    END
  END o[83]
  PIN o[84]
    DIRECTION OUTPUT ;
    USE SIGNAL ;
    PORT
      LAYER M4 ;
        RECT  17.088 10.752 17.28 10.776 ;
    END
  END o[84]
  PIN o[85]
    DIRECTION OUTPUT ;
    USE SIGNAL ;
    PORT
      LAYER M4 ;
        RECT  17.088 10.848 17.28 10.872 ;
    END
  END o[85]
  PIN o[86]
    DIRECTION OUTPUT ;
    USE SIGNAL ;
    PORT
      LAYER M4 ;
        RECT  17.088 10.944 17.28 10.968 ;
    END
  END o[86]
  PIN o[87]
    DIRECTION OUTPUT ;
    USE SIGNAL ;
    PORT
      LAYER M4 ;
        RECT  17.088 11.04 17.28 11.064 ;
    END
  END o[87]
  PIN o[88]
    DIRECTION OUTPUT ;
    USE SIGNAL ;
    PORT
      LAYER M4 ;
        RECT  17.088 11.136 17.28 11.16 ;
    END
  END o[88]
  PIN o[89]
    DIRECTION OUTPUT ;
    USE SIGNAL ;
    PORT
      LAYER M4 ;
        RECT  17.088 11.232 17.28 11.256 ;
    END
  END o[89]
  PIN o[8]
    DIRECTION OUTPUT ;
    USE SIGNAL ;
    PORT
      LAYER M4 ;
        RECT  17.088 3.024 17.28 3.048 ;
    END
  END o[8]
  PIN o[90]
    DIRECTION OUTPUT ;
    USE SIGNAL ;
    PORT
      LAYER M4 ;
        RECT  17.088 11.328 17.28 11.352 ;
    END
  END o[90]
  PIN o[91]
    DIRECTION OUTPUT ;
    USE SIGNAL ;
    PORT
      LAYER M4 ;
        RECT  17.088 11.424 17.28 11.448 ;
    END
  END o[91]
  PIN o[92]
    DIRECTION OUTPUT ;
    USE SIGNAL ;
    PORT
      LAYER M4 ;
        RECT  17.088 11.568 17.28 11.592 ;
    END
  END o[92]
  PIN o[93]
    DIRECTION OUTPUT ;
    USE SIGNAL ;
    PORT
      LAYER M4 ;
        RECT  17.088 11.664 17.28 11.688 ;
    END
  END o[93]
  PIN o[94]
    DIRECTION OUTPUT ;
    USE SIGNAL ;
    PORT
      LAYER M4 ;
        RECT  17.088 11.76 17.28 11.784 ;
    END
  END o[94]
  PIN o[95]
    DIRECTION OUTPUT ;
    USE SIGNAL ;
    PORT
      LAYER M4 ;
        RECT  17.088 11.856 17.28 11.88 ;
    END
  END o[95]
  PIN o[96]
    DIRECTION OUTPUT ;
    USE SIGNAL ;
    PORT
      LAYER M4 ;
        RECT  17.088 11.952 17.28 11.976 ;
    END
  END o[96]
  PIN o[97]
    DIRECTION OUTPUT ;
    USE SIGNAL ;
    PORT
      LAYER M4 ;
        RECT  17.088 12.048 17.28 12.072 ;
    END
  END o[97]
  PIN o[98]
    DIRECTION OUTPUT ;
    USE SIGNAL ;
    PORT
      LAYER M4 ;
        RECT  17.088 12.144 17.28 12.168 ;
    END
  END o[98]
  PIN o[99]
    DIRECTION OUTPUT ;
    USE SIGNAL ;
    PORT
      LAYER M4 ;
        RECT  17.088 12.24 17.28 12.264 ;
    END
  END o[99]
  PIN o[9]
    DIRECTION OUTPUT ;
    USE SIGNAL ;
    PORT
      LAYER M4 ;
        RECT  17.088 3.12 17.28 3.144 ;
    END
  END o[9]
  PIN rs
    DIRECTION INPUT ;
    USE SIGNAL ;
    PORT
      LAYER M5 ;
        RECT  11.856 32.208 11.88 32.4 ;
    END
  END rs
  PIN VDD
    DIRECTION INOUT ;
    USE POWER ;
    PORT
      LAYER M5 ;
        RECT  13.392 2.151 13.512 30.249 ;
        RECT  10.692 2.151 10.812 30.249 ;
        RECT  7.992 2.151 8.112 30.249 ;
        RECT  5.292 2.151 5.412 30.249 ;
        RECT  2.592 2.151 2.712 30.249 ;
    END
  END VDD
  PIN VSS
    DIRECTION INOUT ;
    USE GROUND ;
    PORT
      LAYER M5 ;
        RECT  13.2 2.137 13.32 30.263 ;
        RECT  10.5 2.137 10.62 30.263 ;
        RECT  7.8 2.137 7.92 30.263 ;
        RECT  5.1 2.137 5.22 30.263 ;
        RECT  2.4 2.137 2.52 30.263 ;
    END
  END VSS
  OBS
    LAYER RVTN ;
     RECT  2.16 2.16 15.12 2.295 ;
     RECT  2.16 2.565 15.12 2.835 ;
     RECT  2.16 3.105 15.12 3.375 ;
     RECT  2.16 3.645 15.12 3.915 ;
     RECT  2.16 4.185 15.12 4.455 ;
     RECT  2.16 4.725 15.12 4.995 ;
     RECT  2.16 5.265 15.12 5.535 ;
     RECT  2.16 5.805 15.12 6.075 ;
     RECT  2.16 6.345 15.12 6.615 ;
     RECT  2.16 6.885 15.12 7.155 ;
     RECT  2.16 7.425 15.12 7.695 ;
     RECT  2.16 7.965 15.12 8.235 ;
     RECT  2.16 8.505 15.12 8.775 ;
     RECT  2.16 9.045 15.12 9.315 ;
     RECT  2.16 9.585 15.12 9.855 ;
     RECT  2.16 10.125 15.12 10.395 ;
     RECT  2.16 10.665 15.12 10.935 ;
     RECT  2.16 11.205 15.12 11.475 ;
     RECT  2.16 11.745 15.12 12.015 ;
     RECT  2.16 12.285 15.12 12.555 ;
     RECT  2.16 12.825 15.12 13.095 ;
     RECT  2.16 13.365 15.12 13.635 ;
     RECT  2.16 13.905 15.12 14.175 ;
     RECT  2.16 14.445 15.12 14.715 ;
     RECT  2.16 14.985 15.12 15.255 ;
     RECT  2.16 15.525 15.12 15.795 ;
     RECT  2.16 16.065 15.12 16.335 ;
     RECT  2.16 16.605 15.12 16.875 ;
     RECT  2.16 17.145 15.12 17.415 ;
     RECT  2.16 17.685 15.12 17.955 ;
     RECT  2.16 18.225 15.12 18.495 ;
     RECT  2.16 18.765 15.12 19.035 ;
     RECT  2.16 19.305 15.12 19.575 ;
     RECT  2.16 19.845 15.12 20.115 ;
     RECT  2.16 20.385 15.12 20.655 ;
     RECT  2.16 20.925 15.12 21.195 ;
     RECT  2.16 21.465 15.12 21.735 ;
     RECT  2.16 22.005 15.12 22.275 ;
     RECT  2.16 22.545 15.12 22.815 ;
     RECT  2.16 23.085 15.12 23.355 ;
     RECT  2.16 23.625 15.12 23.895 ;
     RECT  2.16 24.165 15.12 24.435 ;
     RECT  2.16 24.705 15.12 24.975 ;
     RECT  2.16 25.245 15.12 25.515 ;
     RECT  2.16 25.785 15.12 26.055 ;
     RECT  2.16 26.325 15.12 26.595 ;
     RECT  2.16 26.865 15.12 27.135 ;
     RECT  2.16 27.405 15.12 27.675 ;
     RECT  2.16 27.945 15.12 28.215 ;
     RECT  2.16 28.485 15.12 28.755 ;
     RECT  2.16 29.025 15.12 29.295 ;
     RECT  2.16 29.565 15.12 29.835 ;
     RECT  2.16 30.105 15.12 30.24 ;
    LAYER RVTP ;
     RECT  2.16 2.295 15.12 2.565 ;
     RECT  2.16 2.835 15.12 3.105 ;
     RECT  2.16 3.375 15.12 3.645 ;
     RECT  2.16 3.915 15.12 4.185 ;
     RECT  2.16 4.455 15.12 4.725 ;
     RECT  2.16 4.995 15.12 5.265 ;
     RECT  2.16 5.535 15.12 5.805 ;
     RECT  2.16 6.075 15.12 6.345 ;
     RECT  2.16 6.615 15.12 6.885 ;
     RECT  2.16 7.155 15.12 7.425 ;
     RECT  2.16 7.695 15.12 7.965 ;
     RECT  2.16 8.235 15.12 8.505 ;
     RECT  2.16 8.775 15.12 9.045 ;
     RECT  2.16 9.315 15.12 9.585 ;
     RECT  2.16 9.855 15.12 10.125 ;
     RECT  2.16 10.395 15.12 10.665 ;
     RECT  2.16 10.935 15.12 11.205 ;
     RECT  2.16 11.475 15.12 11.745 ;
     RECT  2.16 12.015 15.12 12.285 ;
     RECT  2.16 12.555 15.12 12.825 ;
     RECT  2.16 13.095 15.12 13.365 ;
     RECT  2.16 13.635 15.12 13.905 ;
     RECT  2.16 14.175 15.12 14.445 ;
     RECT  2.16 14.715 15.12 14.985 ;
     RECT  2.16 15.255 15.12 15.525 ;
     RECT  2.16 15.795 15.12 16.065 ;
     RECT  2.16 16.335 15.12 16.605 ;
     RECT  2.16 16.875 15.12 17.145 ;
     RECT  2.16 17.415 15.12 17.685 ;
     RECT  2.16 17.955 15.12 18.225 ;
     RECT  2.16 18.495 15.12 18.765 ;
     RECT  2.16 19.035 15.12 19.305 ;
     RECT  2.16 19.575 15.12 19.845 ;
     RECT  2.16 20.115 15.12 20.385 ;
     RECT  2.16 20.655 15.12 20.925 ;
     RECT  2.16 21.195 15.12 21.465 ;
     RECT  2.16 21.735 15.12 22.005 ;
     RECT  2.16 22.275 15.12 22.545 ;
     RECT  2.16 22.815 15.12 23.085 ;
     RECT  2.16 23.355 15.12 23.625 ;
     RECT  2.16 23.895 15.12 24.165 ;
     RECT  2.16 24.435 15.12 24.705 ;
     RECT  2.16 24.975 15.12 25.245 ;
     RECT  2.16 25.515 15.12 25.785 ;
     RECT  2.16 26.055 15.12 26.325 ;
     RECT  2.16 26.595 15.12 26.865 ;
     RECT  2.16 27.135 15.12 27.405 ;
     RECT  2.16 27.675 15.12 27.945 ;
     RECT  2.16 28.215 15.12 28.485 ;
     RECT  2.16 28.755 15.12 29.025 ;
     RECT  2.16 29.295 15.12 29.565 ;
     RECT  2.16 29.835 15.12 30.105 ;
    LAYER M1 ;
     RECT  2.16 2.151 15.12 30.249 ;
    LAYER M2 ;
     RECT  0.211 9.936 0.311 9.954 ;
     RECT  0.211 20.781 0.311 20.799 ;
     RECT  0.211 23.436 0.311 24.039 ;
     RECT  0.211 25.056 0.311 25.074 ;
     RECT  0.211 28.26 0.311 28.278 ;
     RECT  0.211 17.082 0.535 17.1 ;
     RECT  0.499 21.636 0.535 21.654 ;
     RECT  0.211 3.384 2.16 3.402 ;
     RECT  0.535 4.5 2.16 4.518 ;
     RECT  0.535 11.754 2.16 11.772 ;
     RECT  0.211 13.032 2.16 13.05 ;
     RECT  0.535 17.082 2.16 17.64 ;
     RECT  0.535 18.702 2.16 18.72 ;
     RECT  0.535 21.51 2.16 21.654 ;
     RECT  0.311 23.94 2.16 23.958 ;
     RECT  0.211 27.342 2.16 27.36 ;
     RECT  2.16 2.151 3.199 30.249 ;
     RECT  3.199 2.034 7.051 30.249 ;
     RECT  7.051 2.034 9.383 30.366 ;
     RECT  9.383 2.07 12.487 30.249 ;
     RECT  12.487 1.962 15.12 30.249 ;
     RECT  15.12 1.962 15.431 30.168 ;
     RECT  15.431 9.9 15.467 18.594 ;
     RECT  15.431 1.962 16.007 8.964 ;
     RECT  15.467 9.9 16.007 15.552 ;
     RECT  15.467 16.416 16.007 18.594 ;
     RECT  15.431 19.35 16.007 30.168 ;
     RECT  16.007 1.962 16.043 3.096 ;
     RECT  16.007 19.35 16.043 24.894 ;
     RECT  16.007 9.9 16.079 10.809 ;
     RECT  16.079 9.9 16.511 10.422 ;
     RECT  16.007 11.646 16.511 11.664 ;
     RECT  16.007 12.456 16.511 13.968 ;
     RECT  16.043 19.35 16.511 24.498 ;
     RECT  16.007 26.298 16.511 29.754 ;
     RECT  16.007 16.506 16.519 18.594 ;
     RECT  16.511 19.35 16.519 19.404 ;
     RECT  16.043 1.962 16.547 1.98 ;
     RECT  16.043 3.078 16.547 3.096 ;
     RECT  16.007 3.888 16.547 8.46 ;
     RECT  16.511 9.936 16.547 10.422 ;
     RECT  16.511 12.636 16.547 13.968 ;
     RECT  16.007 14.994 16.547 15.516 ;
     RECT  16.519 16.506 16.547 19.404 ;
     RECT  16.511 20.196 16.547 23.454 ;
     RECT  16.511 26.298 16.547 29.124 ;
     RECT  16.547 4.266 16.583 4.284 ;
     RECT  16.547 5.616 16.583 5.634 ;
     RECT  16.547 6.93 16.583 6.948 ;
     RECT  16.547 10.062 16.583 10.08 ;
     RECT  16.547 13.536 16.583 13.734 ;
     RECT  16.547 20.43 16.583 20.448 ;
     RECT  16.547 21.402 16.583 21.42 ;
     RECT  16.547 8.406 16.619 8.424 ;
     RECT  16.583 13.716 16.619 13.734 ;
     RECT  16.547 18.576 16.619 18.639 ;
     RECT  16.547 19.386 16.619 19.404 ;
     RECT  16.547 16.506 17.087 17.1 ;
     RECT  16.547 27.342 17.087 27.36 ;
    LAYER M3 ;
     RECT  16.524 1.957 16.542 2.029 ;
     RECT  12.492 1.957 12.51 2.065 ;
     RECT  11.88 2.065 12.51 2.101 ;
     RECT  13.788 2.029 13.806 2.101 ;
     RECT  3.204 2.029 3.222 2.143 ;
     RECT  7.2 2.101 7.218 2.143 ;
     RECT  11.88 2.101 12.978 2.143 ;
     RECT  13.788 2.101 13.878 2.143 ;
     RECT  11.88 2.143 13.878 2.191 ;
     RECT  2.415 2.143 3.222 2.203 ;
     RECT  5.115 2.143 5.205 2.263 ;
     RECT  15.984 2.029 16.542 2.263 ;
     RECT  6.084 2.065 6.102 2.299 ;
     RECT  7.2 2.143 7.905 2.299 ;
     RECT  9.36 2.029 9.378 2.299 ;
     RECT  11.88 2.191 14.382 2.299 ;
     RECT  6.084 2.299 9.522 2.335 ;
     RECT  10.515 2.143 10.605 2.335 ;
     RECT  4.824 2.263 5.205 2.347 ;
     RECT  6.084 2.335 10.605 2.371 ;
     RECT  4.824 2.347 5.274 2.413 ;
     RECT  6.084 2.371 10.674 2.413 ;
     RECT  2.304 2.203 3.222 2.461 ;
     RECT  2.304 2.461 3.942 2.533 ;
     RECT  4.824 2.413 10.797 2.533 ;
     RECT  0.252 2.443 0.27 2.621 ;
     RECT  11.736 2.299 14.382 2.633 ;
     RECT  2.304 2.533 10.797 2.641 ;
     RECT  11.736 2.633 11.862 2.641 ;
     RECT  2.304 2.641 11.862 2.669 ;
     RECT  12.6 2.633 14.382 2.725 ;
     RECT  15.408 2.263 16.542 2.725 ;
     RECT  10.404 2.669 11.862 2.759 ;
     RECT  10.404 2.759 10.89 2.795 ;
     RECT  0.396 2.731 0.414 2.861 ;
     RECT  11.844 2.759 11.862 3.029 ;
     RECT  12.6 2.725 16.542 3.065 ;
     RECT  12.816 3.065 16.542 3.101 ;
     RECT  0.216 3.379 0.234 3.485 ;
     RECT  12.816 3.101 16.002 3.569 ;
     RECT  10.515 2.795 10.89 3.595 ;
     RECT  2.304 2.669 9.666 3.643 ;
     RECT  10.515 3.595 11.178 3.643 ;
     RECT  12.816 3.569 15.462 3.835 ;
     RECT  12.6 3.835 15.462 3.839 ;
     RECT  2.304 3.643 11.178 3.869 ;
     RECT  5.115 3.869 11.178 3.875 ;
     RECT  12.6 3.839 14.634 3.875 ;
     RECT  16.524 3.835 16.542 4.261 ;
     RECT  15.408 3.839 15.462 4.351 ;
     RECT  2.304 3.869 4.158 4.459 ;
     RECT  10.515 3.875 11.178 4.651 ;
     RECT  12.06 4.351 12.078 4.651 ;
     RECT  2.196 4.459 4.158 4.657 ;
     RECT  5.115 3.875 9.738 4.657 ;
     RECT  0.54 4.495 0.558 4.685 ;
     RECT  15.408 4.351 15.498 4.693 ;
     RECT  16.524 4.261 16.578 4.693 ;
     RECT  10.515 4.651 12.078 4.757 ;
     RECT  15.408 4.693 16.578 4.781 ;
     RECT  15.408 4.781 15.498 4.829 ;
     RECT  2.196 4.657 9.738 4.843 ;
     RECT  10.515 4.757 10.854 4.843 ;
     RECT  2.196 4.843 10.854 4.919 ;
     RECT  13.032 3.875 14.634 4.939 ;
     RECT  15.408 4.829 15.426 4.939 ;
     RECT  2.304 4.919 10.854 4.955 ;
     RECT  0.252 4.843 0.27 4.973 ;
     RECT  11.736 4.757 12.078 5.224 ;
     RECT  13.032 4.939 15.426 5.224 ;
     RECT  2.304 4.955 9.702 5.261 ;
     RECT  11.736 5.224 15.426 5.261 ;
     RECT  14.22 5.261 15.426 5.333 ;
     RECT  16.524 4.781 16.578 5.639 ;
     RECT  16.524 5.639 16.542 5.659 ;
     RECT  4.068 5.261 9.702 5.701 ;
     RECT  10.515 4.955 10.854 5.755 ;
     RECT  11.736 5.261 13.497 5.755 ;
     RECT  16.488 5.659 16.542 5.755 ;
     RECT  10.515 5.755 13.497 5.909 ;
     RECT  14.22 5.333 14.85 6.091 ;
     RECT  15.984 5.755 16.542 6.091 ;
     RECT  4.068 5.701 9.738 6.277 ;
     RECT  12.708 5.909 13.497 6.277 ;
     RECT  14.22 6.091 16.542 6.277 ;
     RECT  4.032 6.277 9.738 6.571 ;
     RECT  10.515 5.909 11.754 6.571 ;
     RECT  4.032 6.571 11.754 6.719 ;
     RECT  12.708 6.277 16.542 6.797 ;
     RECT  4.032 6.719 10.797 6.809 ;
     RECT  4.032 6.809 9.702 6.893 ;
     RECT  15.948 6.797 16.542 6.925 ;
     RECT  2.304 5.261 3.222 6.961 ;
     RECT  4.032 6.893 9.378 6.961 ;
     RECT  11.52 6.719 11.754 6.961 ;
     RECT  12.708 6.797 14.886 6.961 ;
     RECT  11.52 6.961 14.886 7.079 ;
     RECT  2.304 6.961 9.378 7.088 ;
     RECT  15.948 6.925 16.578 7.133 ;
     RECT  12.312 7.079 12.366 7.151 ;
     RECT  0.252 5.803 0.27 7.325 ;
     RECT  13.176 7.079 14.886 7.349 ;
     RECT  11.52 7.079 11.538 7.385 ;
     RECT  16.488 7.133 16.578 7.517 ;
     RECT  13.212 7.349 14.886 7.591 ;
     RECT  10.515 6.809 10.797 7.735 ;
     RECT  2.304 7.088 9.342 7.861 ;
     RECT  11.592 7.861 11.61 7.963 ;
     RECT  12.348 7.151 12.366 7.963 ;
     RECT  2.304 7.861 9.558 8.041 ;
     RECT  2.304 8.041 9.63 8.107 ;
     RECT  11.592 7.963 12.366 8.167 ;
     RECT  13.212 7.591 15.498 8.167 ;
     RECT  11.592 8.167 15.498 8.195 ;
     RECT  1.26 8.107 1.278 8.203 ;
     RECT  10.515 7.735 10.854 8.251 ;
     RECT  2.304 8.107 9.774 8.275 ;
     RECT  10.515 8.251 11.43 8.275 ;
     RECT  16.488 7.517 16.542 8.401 ;
     RECT  2.304 8.275 11.43 8.429 ;
     RECT  16.488 8.401 16.614 8.525 ;
     RECT  12.312 8.195 15.498 8.537 ;
     RECT  12.348 8.537 15.498 8.671 ;
     RECT  1.152 8.203 1.278 8.765 ;
     RECT  0.324 8.779 0.342 8.827 ;
     RECT  1.152 8.765 1.17 8.861 ;
     RECT  0.252 8.827 0.342 8.957 ;
     RECT  12.348 8.671 16.002 8.969 ;
     RECT  12.348 8.969 13.914 9.005 ;
     RECT  14.832 8.969 16.002 9.149 ;
     RECT  2.304 8.429 9.342 9.247 ;
     RECT  10.515 8.429 10.926 9.247 ;
     RECT  2.304 9.247 10.926 9.341 ;
     RECT  2.304 9.341 10.797 9.347 ;
     RECT  12.6 9.005 13.914 9.347 ;
     RECT  2.304 9.347 9.45 9.383 ;
     RECT  2.304 9.383 3.222 9.643 ;
     RECT  2.268 9.643 3.222 9.689 ;
     RECT  12.6 9.347 13.842 9.787 ;
     RECT  12.276 9.787 13.842 9.895 ;
     RECT  16.524 9.595 16.542 9.895 ;
     RECT  0.252 8.957 0.27 9.916 ;
     RECT  12.024 9.895 13.842 10.049 ;
     RECT  16.488 9.895 16.542 10.057 ;
     RECT  0.216 9.916 0.306 10.109 ;
     RECT  14.832 9.149 15.426 10.123 ;
     RECT  0.252 10.109 0.306 10.157 ;
     RECT  12.204 10.049 13.842 10.193 ;
     RECT  3.96 9.383 9.45 10.267 ;
     RECT  10.515 9.347 10.797 10.267 ;
     RECT  13.215 10.193 13.842 10.315 ;
     RECT  16.488 10.057 16.578 10.349 ;
     RECT  13.215 10.315 14.022 10.363 ;
     RECT  14.832 10.123 15.462 10.363 ;
     RECT  16.488 10.349 16.542 10.427 ;
     RECT  2.304 9.689 3.222 10.471 ;
     RECT  3.96 10.267 10.797 10.471 ;
     RECT  13.215 10.363 15.462 10.651 ;
     RECT  13.215 10.651 16.074 10.814 ;
     RECT  2.304 10.471 10.797 10.867 ;
     RECT  12.204 10.193 12.222 10.939 ;
     RECT  13.215 10.814 16.002 10.939 ;
     RECT  2.304 10.867 10.854 11.165 ;
     RECT  12.204 10.939 16.002 11.173 ;
     RECT  12.132 11.173 16.002 11.641 ;
     RECT  0.252 10.157 0.27 11.749 ;
     RECT  12.132 11.641 16.506 11.749 ;
     RECT  10.515 11.165 10.854 11.785 ;
     RECT  11.844 11.749 16.506 11.785 ;
     RECT  2.304 11.165 9.558 11.947 ;
     RECT  0.252 11.749 0.558 12.029 ;
     RECT  10.515 11.785 16.506 12.119 ;
     RECT  2.304 11.947 9.774 12.631 ;
     RECT  10.515 12.119 14.67 12.631 ;
     RECT  15.408 12.119 16.506 12.631 ;
     RECT  2.304 12.631 14.67 13.019 ;
     RECT  0.252 12.029 0.342 13.027 ;
     RECT  12.636 13.019 14.67 13.027 ;
     RECT  15.408 12.631 16.542 13.027 ;
     RECT  2.304 13.019 9.738 13.085 ;
     RECT  12.636 13.027 16.542 13.091 ;
     RECT  0.216 13.027 0.342 13.133 ;
     RECT  14.256 13.091 16.542 13.199 ;
     RECT  10.515 13.019 11.79 13.289 ;
     RECT  15.408 13.199 16.542 13.325 ;
     RECT  16.524 13.325 16.542 13.531 ;
     RECT  11.592 13.289 11.79 13.559 ;
     RECT  11.772 13.559 11.79 13.667 ;
     RECT  16.524 13.531 16.578 13.708 ;
     RECT  0.252 13.133 0.342 13.853 ;
     RECT  12.636 13.091 13.497 13.864 ;
     RECT  2.304 13.085 9.558 13.865 ;
     RECT  16.524 13.708 16.614 13.901 ;
     RECT  14.256 13.199 14.274 13.963 ;
     RECT  15.408 13.325 15.426 13.963 ;
     RECT  16.524 13.901 16.542 13.973 ;
     RECT  4.032 13.865 9.558 13.981 ;
     RECT  4.032 13.981 9.702 14.107 ;
     RECT  12.024 13.864 13.497 14.143 ;
     RECT  14.256 13.963 15.426 14.143 ;
     RECT  10.515 13.289 10.818 14.189 ;
     RECT  12.024 14.143 15.426 14.243 ;
     RECT  12.672 14.243 15.426 14.341 ;
     RECT  12.672 14.341 16.002 14.369 ;
     RECT  0.252 13.853 0.27 14.573 ;
     RECT  12.888 14.369 16.002 14.779 ;
     RECT  12.888 14.779 16.542 14.819 ;
     RECT  4.032 14.107 9.774 14.917 ;
     RECT  2.304 13.865 3.258 14.923 ;
     RECT  3.996 14.917 9.774 14.923 ;
     RECT  11.736 14.485 11.826 14.957 ;
     RECT  2.304 14.923 9.774 15.025 ;
     RECT  10.515 14.189 10.797 15.025 ;
     RECT  11.52 15.016 11.538 15.053 ;
     RECT  12.888 14.819 14.094 15.151 ;
     RECT  2.304 15.025 10.797 15.179 ;
     RECT  6.336 15.179 10.797 15.197 ;
     RECT  14.832 14.819 16.542 15.521 ;
     RECT  12.564 15.151 14.094 15.547 ;
     RECT  14.832 15.521 16.002 15.557 ;
     RECT  12.456 15.547 14.094 15.601 ;
     RECT  14.832 15.557 15.462 15.601 ;
     RECT  12.456 15.601 15.462 15.629 ;
     RECT  6.372 15.197 10.797 15.719 ;
     RECT  6.372 15.719 9.666 15.997 ;
     RECT  11.916 15.961 11.934 16.061 ;
     RECT  2.304 15.179 5.454 16.219 ;
     RECT  6.336 15.997 9.666 16.219 ;
     RECT  12.744 15.629 15.462 16.315 ;
     RECT  11.952 16.363 11.97 16.375 ;
     RECT  12.744 16.315 16.002 16.375 ;
     RECT  2.304 16.219 9.666 16.507 ;
     RECT  10.476 15.719 10.797 16.507 ;
     RECT  11.952 16.375 16.002 16.529 ;
     RECT  2.304 16.507 10.797 16.673 ;
     RECT  0.252 15.787 0.27 16.829 ;
     RECT  10.476 16.673 10.797 16.891 ;
     RECT  2.304 16.673 9.702 16.943 ;
     RECT  12.276 16.529 16.002 17.069 ;
     RECT  17.064 16.501 17.082 17.165 ;
     RECT  0.216 17.077 0.234 17.213 ;
     RECT  1.152 17.083 1.17 17.213 ;
     RECT  12.42 17.069 16.002 17.419 ;
     RECT  10.476 16.891 11.43 17.581 ;
     RECT  0.252 17.617 0.558 17.693 ;
     RECT  2.304 16.943 9.666 17.761 ;
     RECT  10.476 17.581 11.466 17.761 ;
     RECT  2.304 17.761 11.466 17.851 ;
     RECT  12.42 17.419 16.542 17.851 ;
     RECT  2.304 17.851 16.542 17.888 ;
     RECT  2.304 17.888 11.538 17.915 ;
     RECT  2.304 17.915 9.45 17.987 ;
     RECT  5.004 17.987 9.45 18.032 ;
     RECT  2.304 17.987 4.266 18.185 ;
     RECT  10.476 17.915 11.538 18.185 ;
     RECT  12.42 17.888 16.542 18.365 ;
     RECT  16.524 18.365 16.542 18.571 ;
     RECT  10.476 18.185 10.854 18.599 ;
     RECT  16.524 18.571 16.614 18.644 ;
     RECT  0.252 17.693 0.27 18.653 ;
     RECT  12.42 18.365 15.426 18.661 ;
     RECT  12.132 18.661 15.426 18.689 ;
     RECT  12.132 18.689 14.886 18.701 ;
     RECT  3.744 18.185 4.266 18.725 ;
     RECT  12.132 18.701 12.438 18.749 ;
     RECT  13.212 18.701 14.886 18.761 ;
     RECT  0.54 18.697 0.558 18.845 ;
     RECT  3.96 18.725 4.266 18.955 ;
     RECT  5.115 18.032 9.45 18.955 ;
     RECT  3.96 18.955 9.45 18.967 ;
     RECT  2.304 18.185 2.934 19.039 ;
     RECT  3.96 18.967 9.486 19.201 ;
     RECT  14.832 18.761 14.886 19.265 ;
     RECT  12.204 18.749 12.438 19.337 ;
     RECT  3.96 19.201 9.522 19.339 ;
     RECT  16.524 18.644 16.542 19.339 ;
     RECT  10.476 18.599 10.797 19.381 ;
     RECT  16.488 19.339 16.542 19.381 ;
     RECT  16.488 19.381 16.614 19.469 ;
     RECT  10.476 19.381 11.034 19.471 ;
     RECT  12.204 19.337 12.258 19.471 ;
     RECT  3.96 19.339 9.594 19.483 ;
     RECT  10.476 19.471 12.258 19.483 ;
     RECT  13.212 18.761 13.698 19.483 ;
     RECT  13.032 19.483 13.698 19.579 ;
     RECT  13.032 19.579 13.842 19.615 ;
     RECT  15.408 19.507 15.426 19.615 ;
     RECT  16.488 19.469 16.578 19.615 ;
     RECT  1.152 19.579 1.17 19.805 ;
     RECT  3.96 19.483 12.258 19.877 ;
     RECT  2.304 19.039 3.222 20.011 ;
     RECT  3.96 19.877 11.43 20.011 ;
     RECT  13.032 19.615 14.166 20.047 ;
     RECT  0.252 19.435 0.27 20.155 ;
     RECT  2.304 20.011 11.43 20.309 ;
     RECT  12.24 19.877 12.258 20.333 ;
     RECT  0.252 20.155 0.342 20.381 ;
     RECT  13.032 20.047 14.598 20.389 ;
     RECT  15.408 19.615 16.578 20.389 ;
     RECT  13.032 20.389 16.578 20.443 ;
     RECT  12.492 20.443 16.578 20.453 ;
     RECT  12.492 20.453 16.542 20.489 ;
     RECT  0.252 20.381 0.306 20.764 ;
     RECT  0.216 20.764 0.306 21.053 ;
     RECT  2.304 20.309 10.797 21.293 ;
     RECT  12.996 20.489 16.542 21.397 ;
     RECT  12.636 21.397 16.578 21.433 ;
     RECT  2.376 21.293 10.797 21.569 ;
     RECT  11.916 21.433 16.578 21.739 ;
     RECT  11.7 21.739 16.578 21.767 ;
     RECT  12.744 21.767 16.578 21.821 ;
     RECT  0.504 21.505 0.558 21.835 ;
     RECT  10.296 21.569 10.797 21.928 ;
     RECT  0.252 21.835 0.558 21.965 ;
     RECT  10.296 21.928 10.854 21.979 ;
     RECT  11.7 21.767 11.97 21.979 ;
     RECT  12.744 21.821 16.542 22.001 ;
     RECT  2.376 21.569 9.522 22.075 ;
     RECT  2.304 22.075 9.522 22.081 ;
     RECT  10.296 21.979 11.97 22.109 ;
     RECT  2.268 22.081 9.522 22.205 ;
     RECT  0.504 21.965 0.558 22.267 ;
     RECT  0.504 22.267 0.63 22.301 ;
     RECT  2.304 22.205 9.522 22.349 ;
     RECT  0.612 22.301 0.63 22.397 ;
     RECT  11.7 22.109 11.97 22.603 ;
     RECT  12.744 22.001 13.497 22.603 ;
     RECT  14.256 22.001 16.542 22.649 ;
     RECT  11.7 22.603 13.497 22.795 ;
     RECT  14.256 22.649 14.382 22.795 ;
     RECT  11.7 22.795 14.382 22.811 ;
     RECT  12.456 22.811 14.382 22.829 ;
     RECT  10.296 22.109 10.797 22.843 ;
     RECT  2.304 22.349 9.342 23.131 ;
     RECT  0.288 23.131 0.306 23.179 ;
     RECT  2.304 23.131 9.486 23.179 ;
     RECT  2.304 23.179 9.558 23.275 ;
     RECT  10.296 22.843 11.43 23.275 ;
     RECT  2.196 23.275 11.43 23.315 ;
     RECT  12.816 22.829 14.382 23.315 ;
     RECT  15.408 22.649 16.542 23.459 ;
     RECT  0.216 23.179 0.306 23.467 ;
     RECT  0.216 23.467 0.414 23.597 ;
     RECT  12.996 23.315 14.382 23.611 ;
     RECT  15.408 23.459 16.506 23.611 ;
     RECT  2.304 23.315 11.43 23.645 ;
     RECT  2.304 23.645 10.926 23.657 ;
     RECT  11.88 23.827 11.898 23.927 ;
     RECT  0.216 23.597 0.306 24.044 ;
     RECT  2.304 23.657 10.797 24.089 ;
     RECT  4.032 24.089 9.558 24.125 ;
     RECT  12.996 23.611 16.506 24.205 ;
     RECT  2.304 24.089 3.258 24.317 ;
     RECT  11.952 24.331 12.078 24.368 ;
     RECT  2.34 24.317 3.258 24.395 ;
     RECT  4.032 24.125 9.522 24.395 ;
     RECT  12.852 24.205 16.506 24.431 ;
     RECT  4.032 24.395 9.306 24.503 ;
     RECT  11.952 24.368 11.97 24.503 ;
     RECT  13.104 24.431 16.506 24.503 ;
     RECT  10.296 24.089 10.797 24.871 ;
     RECT  0.252 24.811 0.27 25.051 ;
     RECT  4.14 24.503 9.306 25.141 ;
     RECT  10.188 24.871 10.797 25.141 ;
     RECT  2.412 24.395 3.258 25.177 ;
     RECT  4.14 25.141 10.854 25.177 ;
     RECT  0.216 25.051 0.306 25.229 ;
     RECT  0.252 25.229 0.306 25.277 ;
     RECT  2.412 25.177 3.402 25.291 ;
     RECT  13.104 24.503 16.038 25.435 ;
     RECT  13.032 25.435 16.038 25.469 ;
     RECT  2.304 25.291 3.402 25.475 ;
     RECT  13.032 25.469 16.002 25.681 ;
     RECT  2.415 25.475 3.402 25.825 ;
     RECT  4.14 25.177 10.926 25.825 ;
     RECT  12.636 25.681 16.002 25.861 ;
     RECT  2.415 25.825 10.926 25.951 ;
     RECT  2.415 25.951 11.466 26.051 ;
     RECT  12.348 25.861 16.002 26.221 ;
     RECT  2.415 26.051 11.43 26.248 ;
     RECT  12.24 26.221 16.002 26.251 ;
     RECT  12.24 26.251 16.542 26.285 ;
     RECT  2.304 26.248 11.43 26.573 ;
     RECT  10.296 26.573 11.43 26.897 ;
     RECT  2.304 26.573 9.558 27.095 ;
     RECT  12.492 26.285 16.542 27.139 ;
     RECT  12.168 27.139 16.542 27.211 ;
     RECT  0.252 25.277 0.27 27.337 ;
     RECT  11.88 27.211 16.542 27.337 ;
     RECT  2.34 27.095 9.558 27.355 ;
     RECT  10.296 26.897 10.854 27.355 ;
     RECT  0.216 27.337 0.27 27.389 ;
     RECT  11.88 27.337 17.082 27.389 ;
     RECT  2.34 27.355 10.854 27.679 ;
     RECT  11.88 27.389 16.542 27.68 ;
     RECT  2.34 27.679 10.926 27.751 ;
     RECT  2.34 27.751 11.394 27.835 ;
     RECT  2.304 27.835 11.394 28.175 ;
     RECT  0.252 27.389 0.27 28.252 ;
     RECT  12.384 27.68 16.542 28.283 ;
     RECT  0.216 28.252 0.306 28.397 ;
     RECT  3.996 28.175 11.394 28.417 ;
     RECT  12.384 28.283 13.626 28.417 ;
     RECT  0.252 28.397 0.306 28.445 ;
     RECT  3.996 28.417 13.626 28.445 ;
     RECT  2.304 28.175 3.222 28.651 ;
     RECT  14.472 28.283 16.542 28.787 ;
     RECT  2.268 28.651 3.222 28.823 ;
     RECT  2.304 28.823 3.222 28.921 ;
     RECT  3.996 28.445 10.797 28.921 ;
     RECT  11.772 28.445 13.626 29.101 ;
     RECT  14.472 28.787 15.462 29.101 ;
     RECT  11.772 29.101 15.462 29.129 ;
     RECT  16.488 28.787 16.542 29.129 ;
     RECT  11.844 29.129 15.462 29.291 ;
     RECT  12.924 29.291 15.462 29.309 ;
     RECT  2.304 28.921 10.797 29.363 ;
     RECT  11.844 29.291 12.078 29.693 ;
     RECT  16.488 29.129 16.506 29.759 ;
     RECT  12.924 29.309 15.426 29.831 ;
     RECT  14.256 29.831 15.426 29.939 ;
     RECT  3.96 29.363 10.797 29.987 ;
     RECT  12.924 29.831 13.497 29.987 ;
     RECT  0.252 28.445 0.27 30.029 ;
     RECT  3.96 29.987 10.605 30.029 ;
     RECT  14.292 29.939 15.426 30.035 ;
     RECT  12.924 29.987 13.374 30.043 ;
     RECT  2.304 29.363 3.222 30.065 ;
     RECT  3.96 30.029 4.158 30.065 ;
     RECT  5.115 30.029 10.605 30.077 ;
     RECT  4.14 30.065 4.158 30.101 ;
     RECT  5.115 30.077 5.778 30.101 ;
     RECT  12.564 30.043 13.374 30.101 ;
     RECT  14.292 30.035 14.85 30.125 ;
     RECT  14.292 30.125 14.526 30.137 ;
     RECT  7.056 30.077 10.605 30.173 ;
     RECT  14.436 30.137 14.526 30.179 ;
     RECT  5.115 30.101 5.67 30.209 ;
     RECT  7.056 30.173 9.738 30.209 ;
     RECT  12.564 30.101 13.305 30.209 ;
     RECT  14.436 30.179 14.454 30.209 ;
     RECT  2.304 30.065 2.505 30.221 ;
     RECT  7.056 30.209 8.01 30.221 ;
     RECT  9.324 30.209 9.738 30.221 ;
     RECT  15.984 30.145 16.002 30.221 ;
     RECT  2.415 30.221 2.505 30.257 ;
     RECT  5.115 30.209 5.205 30.257 ;
     RECT  7.056 30.221 7.905 30.257 ;
     RECT  10.515 30.173 10.605 30.257 ;
     RECT  13.215 30.209 13.305 30.257 ;
     RECT  7.056 30.257 7.434 30.299 ;
     RECT  9.324 30.221 9.378 30.299 ;
     RECT  7.056 30.299 7.074 30.371 ;
     RECT  9.36 30.299 9.378 30.371 ;
     RECT  5.4 31.339 5.418 32.268 ;
    LAYER M4 ;
     RECT  0.156 2.208 2.408 30.216 ;
     RECT  2.408 2.148 2.512 30.252 ;
     RECT  2.512 2.304 5.108 30.12 ;
     RECT  5.108 2.148 5.212 30.252 ;
     RECT  5.389 31.344 5.603 31.368 ;
     RECT  5.212 2.304 7.808 30.168 ;
     RECT  7.808 2.148 7.912 30.252 ;
     RECT  7.912 2.304 10.508 30.216 ;
     RECT  10.508 2.148 10.612 30.252 ;
     RECT  10.612 2.304 11.441 30.12 ;
     RECT  11.441 2.304 11.729 23.016 ;
     RECT  11.729 2.304 11.765 21.48 ;
     RECT  11.441 24.336 11.981 30.12 ;
     RECT  11.765 2.544 12.017 21.48 ;
     RECT  12.017 8.688 12.089 21.48 ;
     RECT  11.981 24.336 12.089 27.912 ;
     RECT  12.089 8.688 12.233 16.968 ;
     RECT  12.017 2.544 13.208 7.656 ;
     RECT  12.233 8.688 13.208 10.392 ;
     RECT  12.233 11.376 13.208 16.968 ;
     RECT  12.089 18.672 13.208 21.48 ;
     RECT  11.729 22.608 13.208 23.016 ;
     RECT  12.089 24.624 13.208 27.912 ;
     RECT  11.981 28.944 13.208 30.12 ;
     RECT  13.208 2.148 13.312 30.252 ;
     RECT  13.312 2.418 13.504 30.168 ;
     RECT  13.504 12.864 13.565 12.888 ;
     RECT  13.504 4.176 13.601 5.016 ;
     RECT  13.504 26.736 13.673 27.816 ;
     RECT  13.504 18.048 13.709 18.984 ;
     RECT  13.504 22.8 13.709 22.824 ;
     RECT  13.601 4.176 14.249 4.2 ;
     RECT  13.504 29.232 14.537 30.168 ;
     RECT  13.504 20.112 14.569 21.48 ;
     RECT  13.504 3.12 14.677 3.144 ;
     RECT  14.677 2.736 14.821 3.144 ;
     RECT  13.504 6.288 14.821 6.84 ;
     RECT  13.504 9.312 14.821 9.336 ;
     RECT  13.504 10.32 14.821 10.344 ;
     RECT  13.504 11.328 14.821 11.736 ;
     RECT  14.641 12.864 14.821 12.888 ;
     RECT  13.504 15.744 14.821 17.064 ;
     RECT  13.709 18.048 14.821 18.168 ;
     RECT  14.569 20.064 14.821 21.48 ;
     RECT  13.504 23.856 14.821 23.88 ;
     RECT  13.673 26.736 14.821 26.76 ;
     RECT  13.673 27.792 14.821 27.816 ;
     RECT  14.537 29.232 14.821 30.12 ;
     RECT  14.821 4.944 14.857 7.32 ;
     RECT  14.821 8.592 14.857 12.888 ;
     RECT  14.821 2.736 15.397 3.768 ;
     RECT  14.857 4.944 15.397 12.888 ;
     RECT  14.821 13.968 15.397 22.536 ;
     RECT  14.821 23.616 15.397 30.12 ;
     RECT  15.397 2.304 15.973 30.12 ;
     RECT  15.973 2.208 17.1 30.216 ;
    LAYER M5 ;
     RECT  2.4 2.137 2.52 2.151 ;
     RECT  5.1 2.137 5.22 2.151 ;
     RECT  7.8 2.137 7.92 2.151 ;
     RECT  10.5 2.137 10.62 2.151 ;
     RECT  13.2 2.137 13.32 2.151 ;
     RECT  7.8 2.151 8.112 2.821 ;
     RECT  0.288 2.485 0.312 2.867 ;
     RECT  7.8 2.821 8.232 3.107 ;
     RECT  2.4 2.151 2.712 4.357 ;
     RECT  2.304 4.357 2.712 4.499 ;
     RECT  7.8 3.107 8.112 5.317 ;
     RECT  5.1 2.151 5.412 5.653 ;
     RECT  7.8 5.317 8.232 5.699 ;
     RECT  5.1 5.653 6.744 5.939 ;
     RECT  7.8 5.699 8.112 7.381 ;
     RECT  5.1 5.939 6.312 7.621 ;
     RECT  5.1 7.621 6.696 7.667 ;
     RECT  6.672 7.667 6.696 11.269 ;
     RECT  7.8 7.381 8.232 11.269 ;
     RECT  5.1 7.667 5.412 11.365 ;
     RECT  6.672 11.269 8.232 11.365 ;
     RECT  5.1 11.365 8.232 13.715 ;
     RECT  7.8 13.715 8.232 14.821 ;
     RECT  7.8 14.821 8.28 14.963 ;
     RECT  2.4 4.499 2.712 15.301 ;
     RECT  7.8 14.963 8.232 15.443 ;
     RECT  2.304 15.301 2.712 15.539 ;
     RECT  13.2 2.151 13.512 15.877 ;
     RECT  13.2 15.877 13.656 16.259 ;
     RECT  7.8 15.443 8.112 16.645 ;
     RECT  5.1 13.715 6.12 16.693 ;
     RECT  7.8 16.645 9.048 17.027 ;
     RECT  7.8 17.027 8.232 19.957 ;
     RECT  7.2 19.957 8.232 20.723 ;
     RECT  2.4 15.539 2.712 21.541 ;
     RECT  2.304 21.541 2.712 21.731 ;
     RECT  2.4 21.731 2.712 21.733 ;
     RECT  2.4 21.733 2.856 21.971 ;
     RECT  5.1 16.693 6.168 22.117 ;
     RECT  4.752 22.117 6.168 22.165 ;
     RECT  4.752 22.165 6.552 22.645 ;
     RECT  4.752 22.645 6.744 23.027 ;
     RECT  5.1 23.027 6.744 23.365 ;
     RECT  7.8 20.723 8.232 23.365 ;
     RECT  2.4 21.971 2.712 23.413 ;
     RECT  2.4 23.413 2.808 23.699 ;
     RECT  5.1 23.365 8.232 26.339 ;
     RECT  5.1 26.339 6.552 27.971 ;
     RECT  7.8 26.339 8.232 28.451 ;
     RECT  2.4 23.699 2.712 30.249 ;
     RECT  7.8 28.451 8.112 30.249 ;
     RECT  10.5 2.151 10.812 30.249 ;
     RECT  13.2 16.259 13.512 30.249 ;
     RECT  2.4 30.249 2.52 30.263 ;
     RECT  5.1 27.971 5.592 30.263 ;
     RECT  7.8 30.249 7.92 30.263 ;
     RECT  10.5 30.249 10.62 30.263 ;
     RECT  13.2 30.249 13.32 30.263 ;
     RECT  5.568 30.263 5.592 31.379 ;
     RECT  11.856 29.653 11.88 32.272 ;
  END
END dsfd_dvrlyh_276_WE
END LIBRARY
